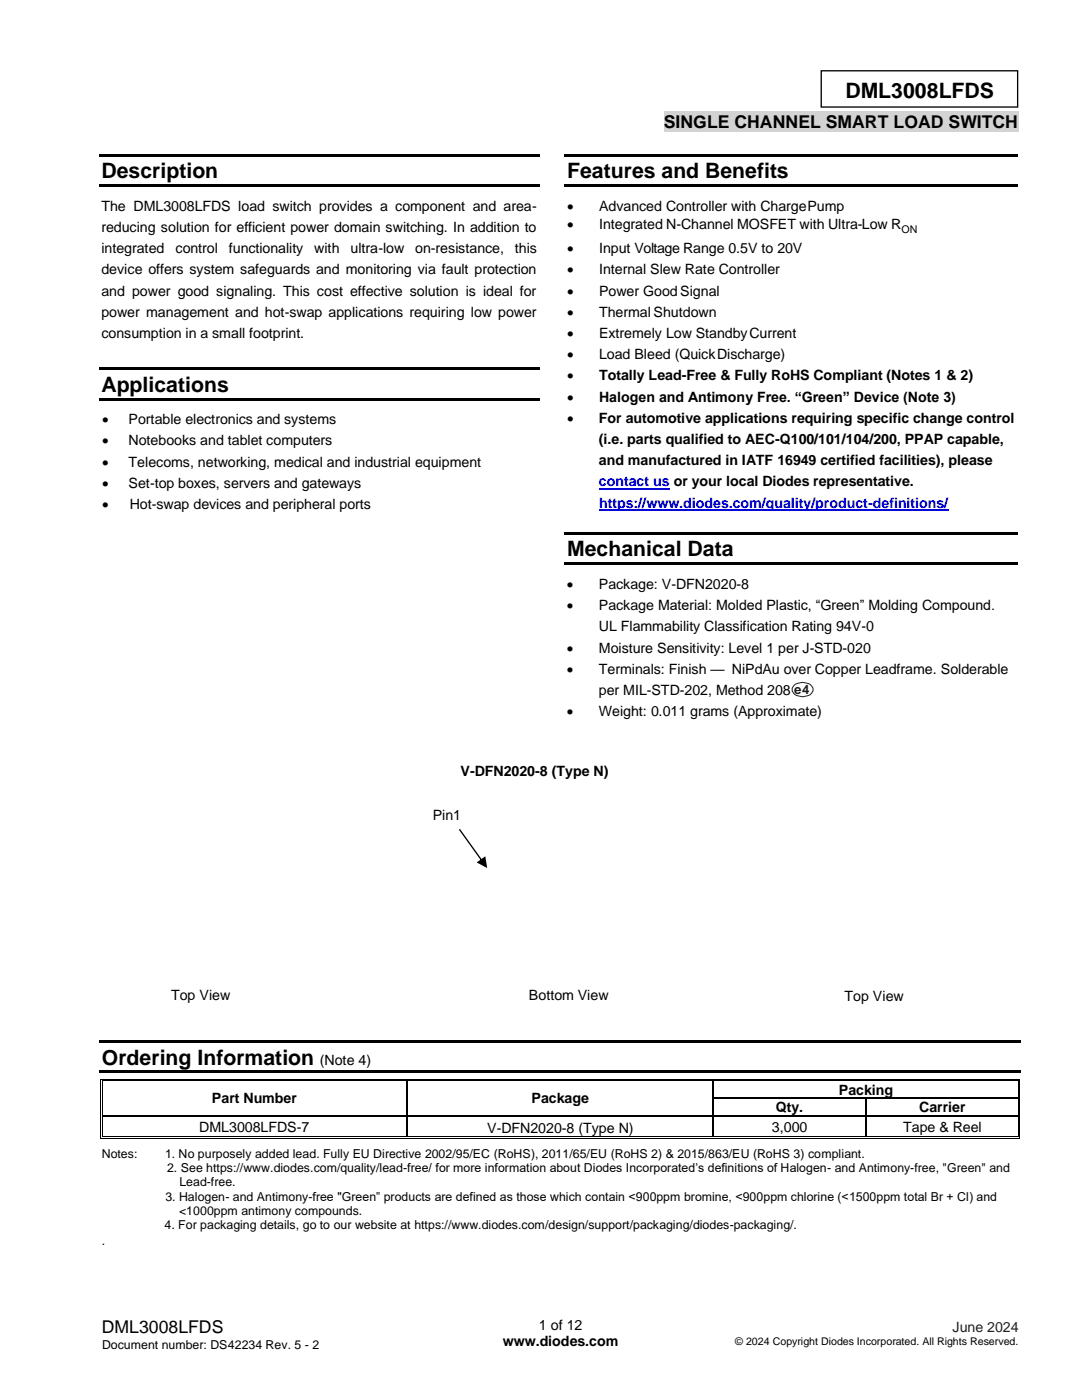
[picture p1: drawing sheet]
<svg xmlns="http://www.w3.org/2000/svg" width="216mm" height="279mm" viewBox="0 0 216 279" stroke-linecap="round" stroke-linejoin="round" font-family="sans-serif">
<defs><g id="words">
<g font-size="4.2">
<text x="168.7" y="19.5">DML3008LFDS</text>
<text x="182.3" y="24.4">6</text>
<text x="20.2" y="35.6">Description</text>
<text x="113.2" y="35.6">Features and Benefits</text>
<text x="20.2" y="78.2">Applications</text>
<text x="113.2" y="111.1">Mechanical Data</text>
<text x="20.3" y="212.5">Ordering Information</text>
</g>
<g font-size="3.5">
<text x="132.5" y="25.6">SINGLE CHANNEL SMART LOAD SWITCH</text>
<text x="20.3" y="266.1">DML3008LFDS</text>
</g>
<g font-size="2.8">
<text x="20.2" y="42">The DML3008LFDS load switch provides a component and area-</text>
<text x="20.2" y="46.3">reducing solution for efficient power domain switching. In addition to</text>
<text x="113.2" y="42">•</text>
<text x="113.2" y="45.7">•</text>
<text x="119.5" y="42">Advanced Controller with ChargePump</text>
<text x="119.5" y="45.7">Integrated N-Channel MOSFET with Ultra-Low R</text>
<text x="20.2" y="50.5">integrated</text>
<text x="35" y="50.5">control</text>
<text x="45.7" y="50.5">functionality</text>
<text x="62.7" y="50.5">with</text>
<text x="69.9" y="50.5">ultra-low</text>
<text x="82.9" y="50.5">on-resistance,</text>
<text x="102.7" y="50.5">this</text>
<text x="113.2" y="50.5">•</text>
<text x="119.5" y="50.5">Input Voltage Range 0.5V to 20V</text>
<text x="20.2" y="54.7">device offers system safeguards and monitoring via fault protection</text>
<text x="20.2" y="59">and power good signaling. This cost effective solution is ideal for</text>
<text x="113.2" y="54.7">•</text>
<text x="113.2" y="59">•</text>
<text x="119.5" y="54.7">Internal Slew Rate Controller</text>
<text x="119.5" y="59">Power Good Signal</text>
<text x="20.2" y="63.2">power management and hot-swap applications requiring low power</text>
<text x="113.2" y="63.2">•</text>
<text x="119.5" y="63.2">Thermal Shutdown</text>
<text x="20.2" y="67.4">consumption in a small footprint.</text>
<text x="113.2" y="67.4">•</text>
<text x="113.2" y="71.7">•</text>
<text x="119.5" y="67.4">Extremely Low StandbyCurrent</text>
<text x="119.5" y="71.7">Load Bleed (QuickDischarge)</text>
<text x="113.2" y="75.9">•</text>
<text x="119.5" y="75.9">Totally Lead-Free &amp; Fully RoHS Compliant (Notes 1 &amp; 2)</text>
<text x="113.2" y="80.1">•</text>
<text x="119.5" y="80.1">Halogen and Antimony Free. “Green” Device (Note 3)</text>
<text x="20.4" y="84.6">•</text>
<text x="20.4" y="88.9">•</text>
<text x="25.7" y="84.6">Portable electronics and systems</text>
<text x="25.7" y="88.9">Notebooks and tablet computers</text>
<text x="113.2" y="84.4">•</text>
<text x="119.5" y="84.4">For automotive applications requiring specific change control</text>
<text x="119.5" y="88.6">(i.e. parts qualified to AEC-Q100/101/104/200, PPAP capable,</text>
<text x="20.4" y="93.1">•</text>
<text x="25.7" y="93.1">Telecoms, networking, medical and industrial equipment</text>
<text x="119.5" y="92.9">and manufactured in IATF 16949 certified facilities), please</text>
<text x="20.4" y="97.3">•</text>
<text x="20.4" y="101.6">•</text>
<text x="25.7" y="97.3">Set-top boxes, servers and gateways</text>
<text x="25.9" y="101.6">Hot-swap devices and peripheral ports</text>
<text x="113.1" y="117.5">•</text>
<text x="119.5" y="117.5">Package: V-DFN2020-8</text>
<text x="113.1" y="121.8">•</text>
<text x="119.5" y="121.8">Package Material: Molded Plastic, “Green” Molding Compound.</text>
<text x="113.1" y="130.2">•</text>
<text x="119.5" y="126">UL Flammability Classification Rating 94V-0</text>
<text x="119.5" y="130.2">Moisture Sensitivity: Level 1 per J-STD-020</text>
<text x="113.1" y="134.5">•</text>
<text x="119.5" y="134.5">Terminals: Finish — NiPdAu over Copper Leadframe. Solderable</text>
<text x="113.1" y="142.9">•</text>
<text x="119.5" y="138.7">per MIL-STD-202, Method 208 e4</text>
<text x="119.5" y="142.9">Weight: 0.011 grams (Approximate)</text>
<text x="91.9" y="155">V-DFN2020-8 (Type N)</text>
<text x="86.3" y="163.6">Pin1</text>
<text x="34.1" y="199.5">Top View</text>
<text x="105.6" y="199.5">Bottom View</text>
<text x="168.5" y="199.8">Top View</text>
<text x="63.8" y="212.5">(Note 4)</text>
<text x="42.3" y="220.2">Part Number</text>
<text x="106.1" y="220.2">Package</text>
<text x="154.8" y="222">Qty.</text>
<text x="167.4" y="218.5">Packing</text>
<text x="183.4" y="222">Carrier</text>
<text x="39.8" y="225.8">DML3008LFDS-7</text>
<text x="97.2" y="226.2">V-DFN2020-8 (Type N)</text>
<text x="154" y="225.8">3,000</text>
<text x="180.2" y="225.8">Tape &amp; Reel</text>
<text x="100.3" y="268.7">www.diodes.com</text>
<text x="107.5" y="265.5">1 of 12</text>
</g>
<g font-size="2.8" fill="#00f">
<text x="119.5" y="97.1">contact us or your local Diodes representative.</text>
<text x="119.5" y="101.3">https://www.diodes.com/quality/product-definitions/</text>
</g>
<text font-size="2.8" fill="#231f20" x="190.1" y="265.8">June 2024</text>
<g font-size="2.5">
<text x="20.3" y="231">Notes:</text>
<text x="32.9" y="231">1. No purposely added lead. Fully EU Directive 2002/95/EC (RoHS), 2011/65/EU (RoHS 2) &amp; 2015/863/EU (RoHS 3) compliant.</text>
<text x="33.3" y="233.9">2. See https://www.diodes.com/quality/lead-free/ for more information about Diodes Incorporated’s definitions of Halogen- and Antimony-free, &quot;Green&quot; and</text>
<text x="33" y="239.6">3. Halogen- and Antimony-free &quot;Green” products are defined as those which contain &lt;900ppm bromine, &lt;900ppm chlorine (&lt;1500ppm total Br + Cl) and</text>
<text x="35.8" y="236.7">Lead-free.</text>
<text x="32.8" y="245.3">4. For packaging details, go to our website at https://www.diodes.com/design/support/packaging/diodes-packaging/.</text>
<text x="35.7" y="242.4">&lt;1000ppm antimony compounds.</text>
<text x="20.3" y="248.4">.</text>
<text x="20.4" y="269.2">Document number: DS42234 Rev. 5 - 2</text>
</g>
<g font-size="2.1">
<text x="179.9" y="46.4">ON</text>
<text x="146.7" y="268.4">© 2024 Copyright Diodes Incorporated. All Rights Reserved.</text>
</g>
</g></defs>
<path d="M163.9 14.1h39.2v7.3h-39.2z" fill="none" stroke="#000" stroke-width=".26"/>
<path d="M132.5 22.3h70.7v4.1h-70.7z" fill-rule="evenodd" fill="#d3d3d3"/>
<g fill="#000">
<path d="M19.7 30.7h87.9v.5h-87.9z" fill-rule="evenodd"/>
<path d="M19.7 36.8h87.9v.5h-87.9z" fill-rule="evenodd"/>
<path d="M112.7 30.7h90.4v.5h-90.4z" fill-rule="evenodd"/>
<path d="M112.7 36.8h90.4v.5h-90.4z" fill-rule="evenodd"/>
<path d="M19.7 73.4h87.9v.5h-87.9z" fill-rule="evenodd"/>
<path d="M19.7 79.4h87.9v.5h-87.9z" fill-rule="evenodd"/>
<path d="M112.7 106.2h90.4v.5h-90.4z" fill-rule="evenodd"/>
<path d="M112.7 112.3h90.4v.5h-90.4z" fill-rule="evenodd"/>
<path d="M19.8 207.6h183.9v.5h-183.9z" fill-rule="evenodd"/>
<path d="M19.8 213.7h183.9v.5h-183.9z" fill-rule="evenodd"/>
<path d="M20 215.3h.2v.5h-.2z" fill-rule="evenodd"/>
<path d="M20 215.3h.5v.2h-.5z" fill-rule="evenodd"/>
<path d="M20 219.1h.2v.2h-.2z" fill-rule="evenodd"/>
<path d="M20.3 215.6h.2v.2h-.2z" fill-rule="evenodd"/>
<path d="M20.3 215.6h.2v.2h-.2z" fill-rule="evenodd"/>
<path d="M20.3 219.1h.2v.2h-.2z" fill-rule="evenodd"/>
<path d="M81.2 215.8h.2z" fill-rule="evenodd"/>
<path d="M81.2 215.3h.5v.2h-.5z" fill-rule="evenodd"/>
<path d="M81.2 215.6h.5v.2h-.5z" fill-rule="evenodd"/>
<path d="M81.2 219.1h.2v.2h-.2z" fill-rule="evenodd"/>
<path d="M142.2 215.8h.2z" fill-rule="evenodd"/>
<path d="M142.2 215.3h.5v.2h-.5z" fill-rule="evenodd"/>
<path d="M142.2 215.6h.5v.2h-.5z" fill-rule="evenodd"/>
<path d="M142.2 219.1h.2v.2h-.2z" fill-rule="evenodd"/>
<path d="M172.7 219.1h.2v.2h-.2z" fill-rule="evenodd"/>
<path d="M203.1 215.3h.5v.2h-.5z" fill-rule="evenodd"/>
<path d="M203.1 215.6h.1v.2h-.1z" fill-rule="evenodd"/>
<path d="M203.1 215.6h.1v.2h-.1z" fill-rule="evenodd"/>
<path d="M203.1 219.1h.1v.2h-.1z" fill-rule="evenodd"/>
<path d="M203.4 215.3h.2v.5h-.2z" fill-rule="evenodd"/>
<path d="M203.4 219.1h.2v.2h-.2z" fill-rule="evenodd"/>
<path d="M20 222.6h.2v.2h-.2z" fill-rule="evenodd"/>
<path d="M20 226.8h.2v.5h-.2z" fill-rule="evenodd"/>
<path d="M20 227.2h.5v.1h-.5z" fill-rule="evenodd"/>
<path d="M20.3 222.6h.2v.2h-.2z" fill-rule="evenodd"/>
<path d="M20.3 226.8h.2v.2h-.2z" fill-rule="evenodd"/>
<path d="M20.3 226.8h.2v.2h-.2z" fill-rule="evenodd"/>
<path d="M81.2 222.6h.2v.2h-.2z" fill-rule="evenodd"/>
<path d="M81.2 226.8h.5v.2h-.5z" fill-rule="evenodd"/>
<path d="M81.2 227.2h.5v.1h-.5z" fill-rule="evenodd"/>
<path d="M142.2 222.6h.2v.2h-.2z" fill-rule="evenodd"/>
<path d="M142.2 226.8h.5v.2h-.5z" fill-rule="evenodd"/>
<path d="M142.2 227.2h.5v.1h-.5z" fill-rule="evenodd"/>
<path d="M172.7 222.6h.2v.2h-.2z" fill-rule="evenodd"/>
<path d="M172.7 226.8h.5v.2h-.5z" fill-rule="evenodd"/>
<path d="M172.7 227.2h.5v.1h-.5z" fill-rule="evenodd"/>
<path d="M203.1 222.6h.1v.2h-.1z" fill-rule="evenodd"/>
<path d="M203.1 227.2h.5v.1h-.5z" fill-rule="evenodd"/>
<path d="M203.1 226.8h.1v.2h-.1z" fill-rule="evenodd"/>
<path d="M203.1 226.8h.1v.2h-.1z" fill-rule="evenodd"/>
<path d="M203.4 222.6h.2v.2h-.2z" fill-rule="evenodd"/>
<path d="M203.4 226.8h.2v.5h-.2z" fill-rule="evenodd"/>
</g>
<path d="M119.5 97.5h14.1M119.5 101.8h69.7" fill="none" stroke="#00f" stroke-width=".3"/>
<g fill="none" stroke="#000" stroke-width=".2">
<path d="M20.1 215.8v3.3M20.1 219.3v3.3M20.4 215.8v3.3M20.4 219.3v3.3M20.5 215.4h60.7M20.5 215.7h60.7M81.7 215.4h60.5M81.7 215.7h60.5M142.7 215.4h60.4M142.7 215.7h60.4M203.2 215.8v3.3M203.2 219.3v3.3"/>
<path d="M203.5 215.8v3.3M203.5 219.3v3.3M20.1 222.8v4M20.4 222.8v4M20.5 227.2h60.7M20.5 226.9h60.7M81.7 227.2h60.5M81.7 226.9h60.5M142.7 227.2h30M142.7 226.9h30M173.2 227.2h29.9M173.2 226.9h29.9"/>
<path d="M203.2 222.8v4M203.5 222.8v4"/>
</g>
<g fill="none" stroke="#000" stroke-width=".25">
<path d="M81.3 215.8v3.3M81.3 219.3v3.3M142.3 215.8v3.3M142.3 219.3v3.3M142.4 219.2h30.3M172.8 219.3v3.3M172.9 219.2h30.2M20.5 222.7h60.7M81.3 222.8v4M81.4 222.7h60.8M142.3 222.8v4M142.4 222.7h30.3"/>
<path d="M172.8 222.8v4M172.9 222.7h30.2"/>
</g>
<path d="M158.6 136.6a2.77 2.77 0 0 1 3.3 .2 1.2 1.2 0 0 1 .2 1.4 1.2 1.2 0 0 1-1.1 .7 2.47 2.47 0 0 1-2.9-1 1.17 1.17 0 0 1 .5-1.3z" fill="none" stroke="#1f1a17" stroke-width=".2"/>
<path d="M91.6 165.6l.2-.2 4.5 6.3-.2 .2zM95.1 172.1l1.7-1.2 .4 2.3z" fill="#000"/>
<use href="#words"/>
</svg>
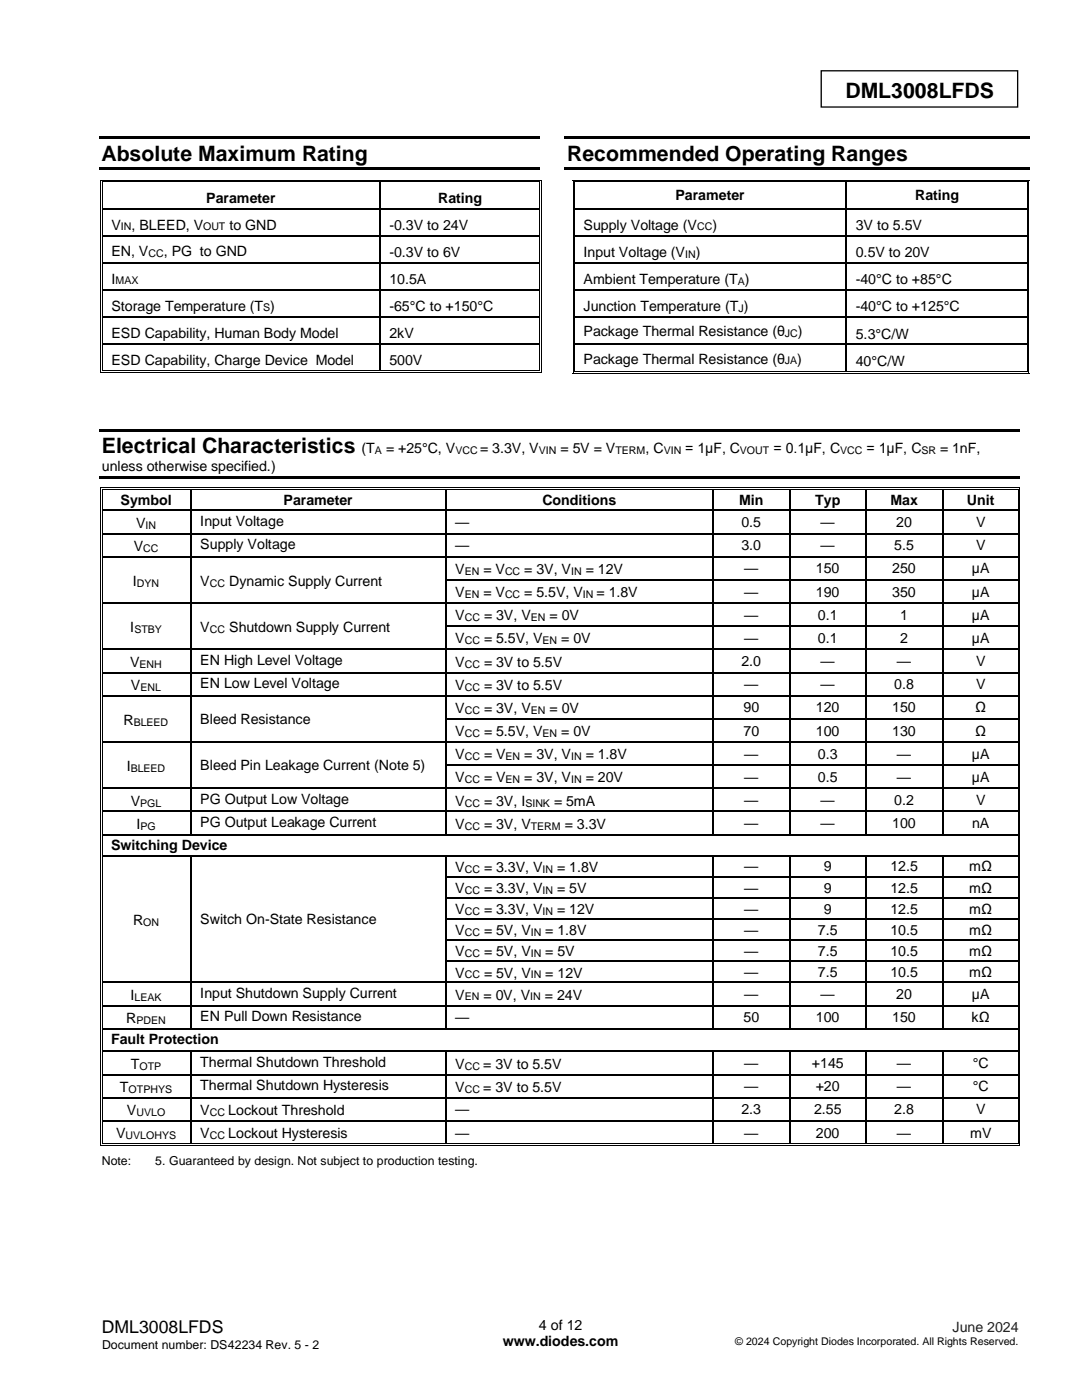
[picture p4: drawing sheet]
<svg xmlns="http://www.w3.org/2000/svg" width="216mm" height="279mm" viewBox="0 0 216 279" stroke-linecap="round" stroke-linejoin="round" font-family="sans-serif">
<defs><g id="words">
<g font-size="4.2">
<text x="168.7" y="19.5">DML3008LFDS</text>
<text x="182.3" y="24.4">6</text>
<text x="20.2" y="32.1">Absolute Maximum Rating</text>
<text x="113.2" y="32.1">Recommended Operating Ranges</text>
<text x="20.3" y="90.4">Electrical Characteristics</text>
</g>
<text font-size="3.5" x="20.3" y="266.1">DML3008LFDS</text>
<g font-size="2.8">
<text x="41.2" y="40.5">Parameter</text>
<text x="87.4" y="40.5">Rating</text>
<text x="134.8" y="40">Parameter</text>
<text x="182.6" y="40">Rating</text>
<text x="22.2" y="45.8">V</text>
<text x="26.3" y="45.8">, BLEED, V</text>
<text x="45.8" y="45.8">to GND</text>
<text x="77.7" y="45.9">-0.3V to 24V</text>
<text x="116.4" y="45.8">Supply Voltage (V</text>
<text x="142.1" y="45.8">)</text>
<text x="170.8" y="45.9">3V to 5.5V</text>
<text x="22.2" y="51.2">EN, V</text>
<text x="32.7" y="51.2">, PG to GND</text>
<text x="77.7" y="51.3">-0.3V to 6V</text>
<text x="116.4" y="51.2">Input Voltage (V</text>
<text x="138.8" y="51.2">)</text>
<text x="170.8" y="51.3">0.5V to 20V</text>
<text x="22.2" y="56.6">I</text>
<text x="77.7" y="56.7">10.5A</text>
<text x="116.4" y="56.6">Ambient Temperature (T )</text>
<text x="170.8" y="56.7">-40°C to +85°C</text>
<text x="22.2" y="62">Storage Temperature (T )</text>
<text x="77.7" y="62.1">-65°C to +150°C</text>
<text x="116.4" y="62.1">Junction Temperature (T )</text>
<text x="170.8" y="62.2">-40°C to +125°C</text>
<text x="22.2" y="67.5">ESD Capability, Human Body Model</text>
<text x="77.7" y="67.5">2kV</text>
<text x="116.4" y="67.1">Package Thermal Resistance (θ</text>
<text x="159.2" y="67.1">)</text>
<text x="170.8" y="67.6">5.3°C/W</text>
<text x="22.2" y="72.9">ESD Capability, Charge Device Model</text>
<text x="77.7" y="72.9">500V</text>
<text x="116.4" y="72.6">Package Thermal Resistance (θ</text>
<text x="159.1" y="72.6">)</text>
<text x="170.8" y="72.9">40°C/W</text>
<text x="20.3" y="94">unless otherwise specified.)</text>
<text x="72.2" y="90.4">(T</text>
<text x="77" y="90.4">= +25°C, V</text>
<text x="95.8" y="90.4">= 3.3V, V</text>
<text x="111.8" y="90.4">= 5V = V</text>
<text x="128.8" y="90.4">, C</text>
<text x="136.7" y="90.4">= 1μF, C</text>
<text x="154.3" y="90.4">= 0.1μF, C</text>
<text x="172.9" y="90.4">= 1μF, C</text>
<text x="187.6" y="90.4">= 1nF,</text>
<text x="24.1" y="100.8">Symbol</text>
<text x="56.6" y="100.8">Parameter</text>
<text x="108.2" y="100.8">Conditions</text>
<text x="147.5" y="100.8">Min</text>
<text x="162.6" y="100.8">Typ</text>
<text x="177.7" y="100.8">Max</text>
<text x="192.9" y="100.8">Unit</text>
<text x="27.1" y="105.3">V</text>
<text x="40" y="105">Input Voltage</text>
<text x="90.8" y="105.2">—</text>
<text x="147.9" y="105.2">0.5</text>
<text x="163.7" y="105.2">—</text>
<text x="178.9" y="105.2">20</text>
<text x="194.8" y="105.2">V</text>
<text x="26.7" y="110">V</text>
<text x="40" y="109.6">Supply Voltage</text>
<text x="90.8" y="109.8">—</text>
<text x="147.9" y="109.8">3.0</text>
<text x="163.7" y="109.8">—</text>
<text x="178.4" y="109.8">5.5</text>
<text x="194.8" y="109.8">V</text>
<text x="26.5" y="116.9">I</text>
<text x="40" y="116.9">V</text>
<text x="45.7" y="116.9">Dynamic Supply Current</text>
<text x="90.8" y="114.6">V</text>
<text x="90.8" y="119.2">V</text>
<text x="96.5" y="114.6">= V</text>
<text x="96.5" y="119.2">= V</text>
<text x="104.6" y="114.6">= 3V, V</text>
<text x="104.6" y="119.2">= 5.5V, V</text>
<text x="116.9" y="114.6">= 12V</text>
<text x="119" y="119.2">= 1.8V</text>
<text x="148.5" y="114.4">—</text>
<text x="148.5" y="119.1">—</text>
<text x="162.8" y="114.4">150</text>
<text x="162.8" y="119.1">190</text>
<text x="178" y="114.4">250</text>
<text x="178" y="119.1">350</text>
<text x="193.9" y="114.4">µA</text>
<text x="193.9" y="119.1">µA</text>
<text x="90.8" y="123.8">V</text>
<text x="96.6" y="123.8">= 3V, V</text>
<text x="109.7" y="123.8">= 0V</text>
<text x="148.5" y="123.7">—</text>
<text x="163.2" y="123.7">0.1</text>
<text x="179.6" y="123.7">1</text>
<text x="193.9" y="123.7">µA</text>
<text x="26" y="126.1">I</text>
<text x="40" y="126.1">V</text>
<text x="45.7" y="126.1">Shutdown Supply Current</text>
<text x="90.8" y="128.4">V</text>
<text x="96.6" y="128.4">= 5.5V, V</text>
<text x="112" y="128.4">= 0V</text>
<text x="148.5" y="128.3">—</text>
<text x="163.2" y="128.3">0.1</text>
<text x="179.6" y="128.3">2</text>
<text x="193.9" y="128.3">µA</text>
<text x="26" y="133.1">V</text>
<text x="26.1" y="137.7">V</text>
<text x="40" y="132.7">EN High Level Voltage</text>
<text x="40" y="137.3">EN Low Level Voltage</text>
<text x="90.8" y="133.1">V</text>
<text x="90.8" y="137.7">V</text>
<text x="96.6" y="133.1">= 3V to 5.5V</text>
<text x="96.6" y="137.7">= 3V to 5.5V</text>
<text x="147.9" y="132.9">2.0</text>
<text x="148.5" y="137.6">—</text>
<text x="163.7" y="132.9">—</text>
<text x="163.7" y="137.6">—</text>
<text x="178.4" y="137.6">0.8</text>
<text x="179" y="132.9">—</text>
<text x="194.8" y="132.9">V</text>
<text x="194.8" y="137.6">V</text>
<text x="90.8" y="142.3">V</text>
<text x="96.6" y="142.3">= 3V, V</text>
<text x="109.7" y="142.3">= 0V</text>
<text x="148.4" y="142.2">90</text>
<text x="162.8" y="142.2">120</text>
<text x="178" y="142.2">150</text>
<text x="194.6" y="142.2">Ω</text>
<text x="24.6" y="144.6">R</text>
<text x="40" y="144.5">Bleed Resistance</text>
<text x="90.8" y="146.9">V</text>
<text x="96.6" y="146.9">= 5.5V, V</text>
<text x="112" y="146.9">= 0V</text>
<text x="148.4" y="146.8">70</text>
<text x="162.8" y="146.8">100</text>
<text x="178" y="146.8">130</text>
<text x="194.6" y="146.8">Ω</text>
<text x="25.3" y="153.9">I</text>
<text x="40" y="153.7">Bleed Pin Leakage Current (Note 5)</text>
<text x="90.8" y="151.5">V</text>
<text x="96.6" y="151.5">= V</text>
<text x="104.6" y="151.5">= 3V, V</text>
<text x="116.9" y="151.5">= 1.8V</text>
<text x="148.5" y="151.4">—</text>
<text x="163.2" y="151.4">0.3</text>
<text x="179" y="151.4">—</text>
<text x="193.9" y="151.4">µA</text>
<text x="26.1" y="160.8">V</text>
<text x="40" y="160.5">PG Output Low Voltage</text>
<text x="90.8" y="156.2">V</text>
<text x="90.8" y="160.8">V</text>
<text x="96.6" y="156.2">= V</text>
<text x="96.6" y="160.8">= 3V, I</text>
<text x="104.6" y="156.2">= 3V, V</text>
<text x="110.5" y="160.8">= 5mA</text>
<text x="116.9" y="156.2">= 20V</text>
<text x="148.5" y="156">—</text>
<text x="148.5" y="160.6">—</text>
<text x="163.2" y="156">0.5</text>
<text x="163.7" y="160.6">—</text>
<text x="178.4" y="160.6">0.2</text>
<text x="179" y="156">—</text>
<text x="193.9" y="156">µA</text>
<text x="194.8" y="160.6">V</text>
<text x="27.2" y="165.4">I</text>
<text x="40" y="165.1">PG Output Leakage Current</text>
<text x="90.8" y="165.4">V</text>
<text x="96.6" y="165.4">= 3V, V</text>
<text x="112.7" y="165.4">= 3.3V</text>
<text x="148.5" y="165.3">—</text>
<text x="163.7" y="165.3">—</text>
<text x="178" y="165.3">100</text>
<text x="194" y="165.3">nA</text>
<text x="22.1" y="169.7">Switching Device</text>
<text x="148.5" y="173.9">—</text>
<text x="164.4" y="173.9">9</text>
<text x="177.7" y="173.9">12.5</text>
<text x="193.4" y="173.9">mΩ</text>
<text x="90.8" y="174">V</text>
<text x="90.8" y="178.2">V</text>
<text x="96.6" y="174">= 3.3V, V</text>
<text x="96.6" y="178.2">= 3.3V, V</text>
<text x="111.2" y="174">= 1.8V</text>
<text x="111.2" y="178.2">= 5V</text>
<text x="148.5" y="178.1">—</text>
<text x="164.4" y="178.1">9</text>
<text x="177.7" y="178.1">12.5</text>
<text x="193.4" y="178.1">mΩ</text>
<text x="26.6" y="184.6">R</text>
<text x="40" y="184.4">Switch On-State Resistance</text>
<text x="90.8" y="182.4">V</text>
<text x="96.6" y="182.4">= 3.3V, V</text>
<text x="111.2" y="182.4">= 12V</text>
<text x="148.5" y="182.4">—</text>
<text x="164.4" y="182.4">9</text>
<text x="177.7" y="182.4">12.5</text>
<text x="193.4" y="182.4">mΩ</text>
<text x="90.8" y="186.7">V</text>
<text x="90.8" y="190.9">V</text>
<text x="96.6" y="186.7">= 5V, V</text>
<text x="96.6" y="190.9">= 5V, V</text>
<text x="108.8" y="186.7">= 1.8V</text>
<text x="108.8" y="190.9">= 5V</text>
<text x="148.5" y="186.5">—</text>
<text x="148.5" y="190.8">—</text>
<text x="163.2" y="186.5">7.5</text>
<text x="163.2" y="190.8">7.5</text>
<text x="177.7" y="186.5">10.5</text>
<text x="177.7" y="190.8">10.5</text>
<text x="193.4" y="186.5">mΩ</text>
<text x="193.4" y="190.8">mΩ</text>
<text x="90.8" y="195.1">V</text>
<text x="96.6" y="195.1">= 5V, V</text>
<text x="108.8" y="195.1">= 12V</text>
<text x="148.5" y="195">—</text>
<text x="163.2" y="195">7.5</text>
<text x="177.7" y="195">10.5</text>
<text x="193.4" y="195">mΩ</text>
<text x="26" y="199.5">I</text>
<text x="40" y="199.2">Input Shutdown Supply Current</text>
<text x="40" y="203.8">EN Pull Down Resistance</text>
<text x="90.8" y="199.5">V</text>
<text x="96.5" y="199.5">= 0V, V</text>
<text x="108.7" y="199.5">= 24V</text>
<text x="148.5" y="199.4">—</text>
<text x="163.7" y="199.4">—</text>
<text x="178.9" y="199.4">20</text>
<text x="193.9" y="199.4">µA</text>
<text x="22.1" y="208.4">Fault Protection</text>
<text x="25.2" y="204.2">R</text>
<text x="90.8" y="204">—</text>
<text x="148.4" y="204">50</text>
<text x="162.8" y="204">100</text>
<text x="178" y="204">150</text>
<text x="193.9" y="204">kΩ</text>
<text x="26.1" y="213.3">T</text>
<text x="40" y="213">Thermal Shutdown Threshold</text>
<text x="90.8" y="213.3">V</text>
<text x="96.4" y="213.3">= 3V to 5.5V</text>
<text x="148.5" y="213.2">—</text>
<text x="162" y="213.2">+145</text>
<text x="179" y="213.2">—</text>
<text x="194.1" y="213.2">°C</text>
<text x="23.9" y="218">T</text>
<text x="40" y="217.6">Thermal Shutdown Hysteresis</text>
<text x="90.8" y="218">V</text>
<text x="96.4" y="218">= 3V to 5.5V</text>
<text x="148.5" y="217.8">—</text>
<text x="162.8" y="217.8">+20</text>
<text x="179" y="217.8">—</text>
<text x="194.1" y="217.8">°C</text>
<text x="23.2" y="227.2">V</text>
<text x="25.3" y="222.6">V</text>
<text x="40" y="222.6">V</text>
<text x="40" y="227.2">V</text>
<text x="45.6" y="222.6">Lockout Threshold</text>
<text x="45.6" y="227.2">Lockout Hysteresis</text>
<text x="90.8" y="222.4">—</text>
<text x="90.8" y="227.1">—</text>
<text x="147.9" y="222.4">2.3</text>
<text x="148.5" y="227.1">—</text>
<text x="162.4" y="222.4">2.55</text>
<text x="162.8" y="227.1">200</text>
<text x="178.4" y="222.4">2.8</text>
<text x="179" y="227.1">—</text>
<text x="193.6" y="227.1">mV</text>
<text x="194.8" y="222.4">V</text>
<text x="100.3" y="268.7">www.diodes.com</text>
<text x="107.5" y="265.5">4 of 12</text>
</g>
<text font-size="2.8" fill="#231f20" x="190.1" y="265.8">June 2024</text>
<g font-size="2.5">
<text x="20.3" y="232.4">Note:</text>
<text x="31" y="232.4">5. Guaranteed by design. Not subject to production testing.</text>
<text x="20.4" y="269.2">Document number: DS42234 Rev. 5 - 2</text>
</g>
<g font-size="2.1">
<text x="24.1" y="46">IN</text>
<text x="40.6" y="46">OUT</text>
<text x="139.1" y="46">CC</text>
<text x="29.6" y="51.4">CC</text>
<text x="136.7" y="51.4">IN</text>
<text x="23" y="56.8">MAX</text>
<text x="147.2" y="56.8">A</text>
<text x="52.5" y="62.2">S</text>
<text x="147.4" y="62.2">J</text>
<text x="156.6" y="67.3">JC</text>
<text x="156.6" y="72.7">JA</text>
<text x="74.8" y="90.6">A</text>
<text x="90.9" y="90.6">VCC</text>
<text x="107.5" y="90.6">VIN</text>
<text x="122.8" y="90.6">TERM</text>
<text x="132.4" y="90.6">VIN</text>
<text x="147.6" y="90.6">VOUT</text>
<text x="167.7" y="90.6">VCC</text>
<text x="183.9" y="90.6">SR</text>
<text x="29" y="105.5">IN</text>
<text x="28.6" y="110.1">CC</text>
<text x="27.3" y="117.1">DYN</text>
<text x="41.9" y="117.1">CC</text>
<text x="92.7" y="114.7">EN</text>
<text x="92.7" y="119.4">EN</text>
<text x="100.8" y="114.7">CC</text>
<text x="100.8" y="119.4">CC</text>
<text x="114" y="114.7">IN</text>
<text x="116.3" y="119.4">IN</text>
<text x="92.7" y="124">CC</text>
<text x="105.9" y="124">EN</text>
<text x="26.8" y="126.3">STBY</text>
<text x="41.9" y="126.3">CC</text>
<text x="92.7" y="128.6">CC</text>
<text x="108.3" y="128.6">EN</text>
<text x="27.9" y="133.2">ENH</text>
<text x="28" y="137.9">ENL</text>
<text x="92.7" y="133.2">CC</text>
<text x="92.7" y="137.9">CC</text>
<text x="92.7" y="142.5">CC</text>
<text x="105.9" y="142.5">EN</text>
<text x="26.7" y="144.8">BLEED</text>
<text x="92.7" y="147.1">CC</text>
<text x="108.3" y="147.1">EN</text>
<text x="26.1" y="154">BLEED</text>
<text x="92.7" y="151.7">CC</text>
<text x="100.9" y="151.7">EN</text>
<text x="114" y="151.7">IN</text>
<text x="28" y="161">PGL</text>
<text x="92.7" y="156.3">CC</text>
<text x="92.7" y="161">CC</text>
<text x="100.9" y="156.3">EN</text>
<text x="104.8" y="161">SINK</text>
<text x="114" y="156.3">IN</text>
<text x="28" y="165.6">PG</text>
<text x="92.7" y="165.6">CC</text>
<text x="105.9" y="165.6">TERM</text>
<text x="92.7" y="174.2">CC</text>
<text x="92.7" y="178.4">CC</text>
<text x="108.3" y="174.2">IN</text>
<text x="108.3" y="178.4">IN</text>
<text x="28.6" y="184.8">ON</text>
<text x="92.7" y="182.6">CC</text>
<text x="108.3" y="182.6">IN</text>
<text x="92.7" y="186.8">CC</text>
<text x="92.7" y="191">CC</text>
<text x="105.9" y="186.8">IN</text>
<text x="105.9" y="191">IN</text>
<text x="92.7" y="195.3">CC</text>
<text x="105.9" y="195.3">IN</text>
<text x="26.8" y="199.7">LEAK</text>
<text x="92.7" y="199.7">EN</text>
<text x="105.8" y="199.7">IN</text>
<text x="27.2" y="204.3">PDEN</text>
<text x="27.8" y="213.5">OTP</text>
<text x="92.7" y="213.5">CC</text>
<text x="25.7" y="218.1">OTPHYS</text>
<text x="92.7" y="218.1">CC</text>
<text x="25.1" y="227.4">UVLOHYS</text>
<text x="27.2" y="222.8">UVLO</text>
<text x="41.9" y="222.8">CC</text>
<text x="41.9" y="227.4">CC</text>
<text x="146.7" y="268.4">© 2024 Copyright Diodes Incorporated. All Rights Reserved.</text>
</g>
</g></defs>
<path d="M163.9 14.1h39.2v7.3h-39.2z" fill="none" stroke="#000" stroke-width=".26"/>
<g fill="#000">
<path d="M19.7 27.2h87.9v.5h-87.9z" fill-rule="evenodd"/>
<path d="M19.7 33.3h87.9v.5h-87.9z" fill-rule="evenodd"/>
<path d="M20.1 35.9h.1v.5h-.1z" fill-rule="evenodd"/>
<path d="M20.1 35.9h.5v.1h-.5z" fill-rule="evenodd"/>
<path d="M20.4 36.2h.2v.2h-.2z" fill-rule="evenodd"/>
<path d="M20.4 36.2h.2v.2h-.2z" fill-rule="evenodd"/>
<path d="M75.7 36.4h.2z" fill-rule="evenodd"/>
<path d="M75.7 35.9h.5v.1h-.5z" fill-rule="evenodd"/>
<path d="M75.7 36.2h.5v.2h-.5z" fill-rule="evenodd"/>
<path d="M107.6 35.9h.5v.1h-.5z" fill-rule="evenodd"/>
<path d="M107.6 36.2h.2v.2h-.2z" fill-rule="evenodd"/>
<path d="M107.6 36.2h.2v.2h-.2z" fill-rule="evenodd"/>
<path d="M107.9 35.9h.2v.5h-.2z" fill-rule="evenodd"/>
<path d="M112.7 27.2h92.7v.5h-92.7z" fill-rule="evenodd"/>
<path d="M112.7 33.3h92.7v.5h-92.7z" fill-rule="evenodd"/>
<path d="M114.3 35.9h.1v.5h-.1z" fill-rule="evenodd"/>
<path d="M114.3 35.9h.5v.1h-.5z" fill-rule="evenodd"/>
<path d="M114.6 36.2h.2v.2h-.2z" fill-rule="evenodd"/>
<path d="M114.6 36.2h.2v.2h-.2z" fill-rule="evenodd"/>
<path d="M168.7 36.4h.3z" fill-rule="evenodd"/>
<path d="M168.7 35.9h.5v.1h-.5z" fill-rule="evenodd"/>
<path d="M168.7 36.2h.5v.2h-.5z" fill-rule="evenodd"/>
<path d="M204.9 35.9h.5v.1h-.5z" fill-rule="evenodd"/>
<path d="M204.9 36.2h.2v.2h-.2z" fill-rule="evenodd"/>
<path d="M204.9 36.2h.2v.2h-.2z" fill-rule="evenodd"/>
<path d="M205.2 35.9h.2v.5h-.2z" fill-rule="evenodd"/>
<path d="M20.1 41.5h.1v.3h-.1z" fill-rule="evenodd"/>
<path d="M20.1 46.9h.1v.3h-.1z" fill-rule="evenodd"/>
<path d="M20.1 52.3h.1v.3h-.1z" fill-rule="evenodd"/>
<path d="M20.1 57.7h.1v.3h-.1z" fill-rule="evenodd"/>
<path d="M20.4 41.5h.2v.3h-.2z" fill-rule="evenodd"/>
<path d="M20.4 46.9h.2v.3h-.2z" fill-rule="evenodd"/>
<path d="M20.4 52.3h.2v.3h-.2z" fill-rule="evenodd"/>
<path d="M20.4 57.7h.2v.3h-.2z" fill-rule="evenodd"/>
<path d="M75.7 41.5h.2v.3h-.2z" fill-rule="evenodd"/>
<path d="M75.7 46.9h.2v.3h-.2z" fill-rule="evenodd"/>
<path d="M75.7 52.3h.2v.3h-.2z" fill-rule="evenodd"/>
<path d="M75.7 57.7h.2v.3h-.2z" fill-rule="evenodd"/>
<path d="M107.6 41.5h.2v.3h-.2z" fill-rule="evenodd"/>
<path d="M107.6 46.9h.2v.3h-.2z" fill-rule="evenodd"/>
<path d="M107.6 52.3h.2v.3h-.2z" fill-rule="evenodd"/>
<path d="M107.6 57.7h.2v.3h-.2z" fill-rule="evenodd"/>
<path d="M107.9 41.5h.2v.3h-.2z" fill-rule="evenodd"/>
<path d="M107.9 46.9h.2v.3h-.2z" fill-rule="evenodd"/>
<path d="M107.9 52.3h.2v.3h-.2z" fill-rule="evenodd"/>
<path d="M107.9 57.7h.2v.3h-.2z" fill-rule="evenodd"/>
<path d="M114.3 41.5h.1v.3h-.1z" fill-rule="evenodd"/>
<path d="M114.3 47h.1v.2h-.1z" fill-rule="evenodd"/>
<path d="M114.3 52.4h.1v.2h-.1z" fill-rule="evenodd"/>
<path d="M114.3 57.8h.1v.2h-.1z" fill-rule="evenodd"/>
<path d="M114.6 41.5h.2v.3h-.2z" fill-rule="evenodd"/>
<path d="M114.6 47h.2v.2h-.2z" fill-rule="evenodd"/>
<path d="M114.6 52.4h.2v.2h-.2z" fill-rule="evenodd"/>
<path d="M114.6 57.8h.2v.2h-.2z" fill-rule="evenodd"/>
<path d="M168.7 41.5h.3v.3h-.3z" fill-rule="evenodd"/>
<path d="M168.7 47h.3v.2h-.3z" fill-rule="evenodd"/>
<path d="M168.7 52.4h.3v.2h-.3z" fill-rule="evenodd"/>
<path d="M168.7 57.8h.3v.2h-.3z" fill-rule="evenodd"/>
<path d="M204.9 41.5h.2v.3h-.2z" fill-rule="evenodd"/>
<path d="M204.9 47h.2v.2h-.2z" fill-rule="evenodd"/>
<path d="M204.9 52.4h.2v.2h-.2z" fill-rule="evenodd"/>
<path d="M204.9 57.8h.2v.2h-.2z" fill-rule="evenodd"/>
<path d="M205.2 41.5h.2v.3h-.2z" fill-rule="evenodd"/>
<path d="M205.2 47h.2v.2h-.2z" fill-rule="evenodd"/>
<path d="M205.2 52.4h.2v.2h-.2z" fill-rule="evenodd"/>
<path d="M205.2 57.8h.2v.2h-.2z" fill-rule="evenodd"/>
<path d="M20.1 63.1h.1v.3h-.1z" fill-rule="evenodd"/>
<path d="M20.1 68.5h.1v.3h-.1z" fill-rule="evenodd"/>
<path d="M20.1 73.9h.1v.5h-.1z" fill-rule="evenodd"/>
<path d="M20.1 74.3h.5v.1h-.5z" fill-rule="evenodd"/>
<path d="M20.4 63.1h.2v.3h-.2z" fill-rule="evenodd"/>
<path d="M20.4 68.5h.2v.3h-.2z" fill-rule="evenodd"/>
<path d="M20.4 73.9h.2v.2h-.2z" fill-rule="evenodd"/>
<path d="M20.4 73.9h.2v.2h-.2z" fill-rule="evenodd"/>
<path d="M75.7 63.1h.2v.3h-.2z" fill-rule="evenodd"/>
<path d="M75.7 68.5h.2v.3h-.2z" fill-rule="evenodd"/>
<path d="M75.7 73.9h.5v.2h-.5z" fill-rule="evenodd"/>
<path d="M75.7 74.3h.5v.1h-.5z" fill-rule="evenodd"/>
<path d="M107.6 63.1h.2v.3h-.2z" fill-rule="evenodd"/>
<path d="M107.6 68.5h.2v.3h-.2z" fill-rule="evenodd"/>
<path d="M107.6 74.3h.5v.1h-.5z" fill-rule="evenodd"/>
<path d="M107.6 73.9h.2v.2h-.2z" fill-rule="evenodd"/>
<path d="M107.6 73.9h.2v.2h-.2z" fill-rule="evenodd"/>
<path d="M107.9 63.1h.2v.3h-.2z" fill-rule="evenodd"/>
<path d="M107.9 68.5h.2v.3h-.2z" fill-rule="evenodd"/>
<path d="M107.9 73.9h.2v.5h-.2z" fill-rule="evenodd"/>
<path d="M114.3 63.2h.1v.2h-.1z" fill-rule="evenodd"/>
<path d="M114.3 68.6h.1v.2h-.1z" fill-rule="evenodd"/>
<path d="M114.3 74h.1v.6h-.1z" fill-rule="evenodd"/>
<path d="M114.3 74.4h.5v.2h-.5z" fill-rule="evenodd"/>
<path d="M114.6 63.2h.2v.2h-.2z" fill-rule="evenodd"/>
<path d="M114.6 68.6h.2v.2h-.2z" fill-rule="evenodd"/>
<path d="M114.6 74h.2v.2h-.2z" fill-rule="evenodd"/>
<path d="M114.6 74h.2v.2h-.2z" fill-rule="evenodd"/>
<path d="M168.7 63.2h.3v.2h-.3z" fill-rule="evenodd"/>
<path d="M168.7 68.6h.3v.2h-.3z" fill-rule="evenodd"/>
<path d="M168.7 74h.5v.2h-.5z" fill-rule="evenodd"/>
<path d="M168.7 74.4h.5v.2h-.5z" fill-rule="evenodd"/>
<path d="M204.9 63.2h.2v.2h-.2z" fill-rule="evenodd"/>
<path d="M204.9 68.6h.2v.2h-.2z" fill-rule="evenodd"/>
<path d="M204.9 74.4h.5v.2h-.5z" fill-rule="evenodd"/>
<path d="M204.9 74h.2v.2h-.2z" fill-rule="evenodd"/>
<path d="M204.9 74h.2v.2h-.2z" fill-rule="evenodd"/>
<path d="M205.2 63.2h.2v.2h-.2z" fill-rule="evenodd"/>
<path d="M205.2 68.6h.2v.2h-.2z" fill-rule="evenodd"/>
<path d="M205.2 74h.2v.6h-.2z" fill-rule="evenodd"/>
<path d="M19.8 85.6h183.7v.5h-183.7z" fill-rule="evenodd"/>
<path d="M19.8 95h183.7v.5h-183.7z" fill-rule="evenodd"/>
<path d="M20 97.3h.2v.5h-.2z" fill-rule="evenodd"/>
<path d="M20 97.3h.5v.1h-.5z" fill-rule="evenodd"/>
<path d="M20.3 97.6h.2v.2h-.2z" fill-rule="evenodd"/>
<path d="M20.3 97.6h.2v.2h-.2z" fill-rule="evenodd"/>
<path d="M37.9 97.8h.3z" fill-rule="evenodd"/>
<path d="M37.9 97.3h.5v.1h-.5z" fill-rule="evenodd"/>
<path d="M37.9 97.6h.5v.2h-.5z" fill-rule="evenodd"/>
<path d="M88.8 97.8h.2z" fill-rule="evenodd"/>
<path d="M88.8 97.3h.5v.1h-.5z" fill-rule="evenodd"/>
<path d="M88.8 97.6h.5v.2h-.5z" fill-rule="evenodd"/>
<path d="M142.2 97.8h.2z" fill-rule="evenodd"/>
<path d="M142.2 97.3h.5v.1h-.5z" fill-rule="evenodd"/>
<path d="M142.2 97.6h.5v.2h-.5z" fill-rule="evenodd"/>
<path d="M157.4 97.8h.3z" fill-rule="evenodd"/>
<path d="M157.4 97.3h.5v.1h-.5z" fill-rule="evenodd"/>
<path d="M157.4 97.6h.5v.2h-.5z" fill-rule="evenodd"/>
<path d="M172.7 97.8h.2z" fill-rule="evenodd"/>
<path d="M172.7 97.3h.5v.1h-.5z" fill-rule="evenodd"/>
<path d="M172.7 97.6h.5v.2h-.5z" fill-rule="evenodd"/>
<path d="M188 97.8h.2z" fill-rule="evenodd"/>
<path d="M188 97.3h.5v.1h-.5z" fill-rule="evenodd"/>
<path d="M188 97.6h.5v.2h-.5z" fill-rule="evenodd"/>
<path d="M203.1 97.3h.5v.1h-.5z" fill-rule="evenodd"/>
<path d="M203.1 97.6h.1v.2h-.1z" fill-rule="evenodd"/>
<path d="M203.1 97.6h.1v.2h-.1z" fill-rule="evenodd"/>
<path d="M203.4 97.3h.2v.5h-.2z" fill-rule="evenodd"/>
<path d="M20 101.7h.2v.3h-.2z" fill-rule="evenodd"/>
<path d="M20 106.4h.2v.2h-.2z" fill-rule="evenodd"/>
<path d="M20 111h.2v.2h-.2z" fill-rule="evenodd"/>
<path d="M20 115.6h.2v.2h-.2z" fill-rule="evenodd"/>
<path d="M20.3 101.7h.2v.3h-.2z" fill-rule="evenodd"/>
<path d="M20.3 106.4h.2v.2h-.2z" fill-rule="evenodd"/>
<path d="M20.3 111h.2v.2h-.2z" fill-rule="evenodd"/>
<path d="M20.3 115.6h.2v.2h-.2z" fill-rule="evenodd"/>
<path d="M37.9 101.7h.3v.3h-.3z" fill-rule="evenodd"/>
<path d="M37.9 106.4h.3v.2h-.3z" fill-rule="evenodd"/>
<path d="M37.9 111h.3v.2h-.3z" fill-rule="evenodd"/>
<path d="M37.9 115.6h.3v.2h-.3z" fill-rule="evenodd"/>
<path d="M88.8 101.7h.2v.3h-.2z" fill-rule="evenodd"/>
<path d="M88.8 106.4h.2v.2h-.2z" fill-rule="evenodd"/>
<path d="M88.8 111h.2v.2h-.2z" fill-rule="evenodd"/>
<path d="M88.8 115.6h.2v.2h-.2z" fill-rule="evenodd"/>
<path d="M142.2 101.7h.2v.3h-.2z" fill-rule="evenodd"/>
<path d="M142.2 106.4h.2v.2h-.2z" fill-rule="evenodd"/>
<path d="M142.2 111h.2v.2h-.2z" fill-rule="evenodd"/>
<path d="M142.2 115.6h.2v.2h-.2z" fill-rule="evenodd"/>
<path d="M157.4 101.7h.3v.3h-.3z" fill-rule="evenodd"/>
<path d="M157.4 106.4h.3v.2h-.3z" fill-rule="evenodd"/>
<path d="M157.4 111h.3v.2h-.3z" fill-rule="evenodd"/>
<path d="M157.4 115.6h.3v.2h-.3z" fill-rule="evenodd"/>
<path d="M172.7 101.7h.2v.3h-.2z" fill-rule="evenodd"/>
<path d="M172.7 106.4h.2v.2h-.2z" fill-rule="evenodd"/>
<path d="M172.7 111h.2v.2h-.2z" fill-rule="evenodd"/>
<path d="M172.7 115.6h.2v.2h-.2z" fill-rule="evenodd"/>
<path d="M188 101.7h.2v.3h-.2z" fill-rule="evenodd"/>
<path d="M188 106.4h.2v.2h-.2z" fill-rule="evenodd"/>
<path d="M188 111h.2v.2h-.2z" fill-rule="evenodd"/>
<path d="M188 115.6h.2v.2h-.2z" fill-rule="evenodd"/>
<path d="M203.1 101.7h.1v.3h-.1z" fill-rule="evenodd"/>
<path d="M203.1 106.4h.1v.2h-.1z" fill-rule="evenodd"/>
<path d="M203.1 111h.1v.2h-.1z" fill-rule="evenodd"/>
<path d="M203.1 115.6h.1v.2h-.1z" fill-rule="evenodd"/>
<path d="M203.4 101.7h.2v.3h-.2z" fill-rule="evenodd"/>
<path d="M203.4 106.4h.2v.2h-.2z" fill-rule="evenodd"/>
<path d="M203.4 111h.2v.2h-.2z" fill-rule="evenodd"/>
<path d="M203.4 115.6h.2v.2h-.2z" fill-rule="evenodd"/>
<path d="M20 120.2h.2v.3h-.2z" fill-rule="evenodd"/>
<path d="M20 124.8h.2v.3h-.2z" fill-rule="evenodd"/>
<path d="M20 129.4h.2v.3h-.2z" fill-rule="evenodd"/>
<path d="M20 134.1h.2v.2h-.2z" fill-rule="evenodd"/>
<path d="M20 138.7h.2v.3h-.2z" fill-rule="evenodd"/>
<path d="M20.3 120.2h.2v.3h-.2z" fill-rule="evenodd"/>
<path d="M20.3 124.8h.2v.3h-.2z" fill-rule="evenodd"/>
<path d="M20.3 129.4h.2v.3h-.2z" fill-rule="evenodd"/>
<path d="M20.3 134.1h.2v.2h-.2z" fill-rule="evenodd"/>
<path d="M20.3 138.7h.2v.3h-.2z" fill-rule="evenodd"/>
<path d="M37.9 120.2h.3v.3h-.3z" fill-rule="evenodd"/>
<path d="M37.9 124.8h.3v.3h-.3z" fill-rule="evenodd"/>
<path d="M37.9 129.4h.3v.3h-.3z" fill-rule="evenodd"/>
<path d="M37.9 134.1h.3v.2h-.3z" fill-rule="evenodd"/>
<path d="M37.9 138.7h.3v.3h-.3z" fill-rule="evenodd"/>
<path d="M88.8 120.2h.2v.3h-.2z" fill-rule="evenodd"/>
<path d="M88.8 124.8h.2v.3h-.2z" fill-rule="evenodd"/>
<path d="M88.8 129.4h.2v.3h-.2z" fill-rule="evenodd"/>
<path d="M88.8 134.1h.2v.2h-.2z" fill-rule="evenodd"/>
<path d="M88.8 138.7h.2v.3h-.2z" fill-rule="evenodd"/>
<path d="M142.2 120.2h.2v.3h-.2z" fill-rule="evenodd"/>
<path d="M142.2 124.8h.2v.3h-.2z" fill-rule="evenodd"/>
<path d="M142.2 129.4h.2v.3h-.2z" fill-rule="evenodd"/>
<path d="M142.2 134.1h.2v.2h-.2z" fill-rule="evenodd"/>
<path d="M142.2 138.7h.2v.3h-.2z" fill-rule="evenodd"/>
<path d="M157.4 120.2h.3v.3h-.3z" fill-rule="evenodd"/>
<path d="M157.4 124.8h.3v.3h-.3z" fill-rule="evenodd"/>
<path d="M157.4 129.4h.3v.3h-.3z" fill-rule="evenodd"/>
<path d="M157.4 134.1h.3v.2h-.3z" fill-rule="evenodd"/>
<path d="M157.4 138.7h.3v.3h-.3z" fill-rule="evenodd"/>
<path d="M172.7 120.2h.2v.3h-.2z" fill-rule="evenodd"/>
<path d="M172.7 124.8h.2v.3h-.2z" fill-rule="evenodd"/>
<path d="M172.7 129.4h.2v.3h-.2z" fill-rule="evenodd"/>
<path d="M172.7 134.1h.2v.2h-.2z" fill-rule="evenodd"/>
<path d="M172.7 138.7h.2v.3h-.2z" fill-rule="evenodd"/>
<path d="M188 120.2h.2v.3h-.2z" fill-rule="evenodd"/>
<path d="M188 124.8h.2v.3h-.2z" fill-rule="evenodd"/>
<path d="M188 129.4h.2v.3h-.2z" fill-rule="evenodd"/>
<path d="M188 134.1h.2v.2h-.2z" fill-rule="evenodd"/>
<path d="M188 138.7h.2v.3h-.2z" fill-rule="evenodd"/>
<path d="M203.1 120.2h.1v.3h-.1z" fill-rule="evenodd"/>
<path d="M203.1 124.8h.1v.3h-.1z" fill-rule="evenodd"/>
<path d="M203.1 129.4h.1v.3h-.1z" fill-rule="evenodd"/>
<path d="M203.1 134.1h.1v.2h-.1z" fill-rule="evenodd"/>
<path d="M203.1 138.7h.1v.3h-.1z" fill-rule="evenodd"/>
<path d="M203.4 120.2h.2v.3h-.2z" fill-rule="evenodd"/>
<path d="M203.4 124.8h.2v.3h-.2z" fill-rule="evenodd"/>
<path d="M203.4 129.4h.2v.3h-.2z" fill-rule="evenodd"/>
<path d="M203.4 134.1h.2v.2h-.2z" fill-rule="evenodd"/>
<path d="M203.4 138.7h.2v.3h-.2z" fill-rule="evenodd"/>
<path d="M20 143.3h.2v.3h-.2z" fill-rule="evenodd"/>
<path d="M20 147.9h.2v.3h-.2z" fill-rule="evenodd"/>
<path d="M20 152.5h.2v.3h-.2z" fill-rule="evenodd"/>
<path d="M20 157.2h.2v.2h-.2z" fill-rule="evenodd"/>
<path d="M20.3 143.3h.2v.3h-.2z" fill-rule="evenodd"/>
<path d="M20.3 147.9h.2v.3h-.2z" fill-rule="evenodd"/>
<path d="M20.3 152.5h.2v.3h-.2z" fill-rule="evenodd"/>
<path d="M20.3 157.2h.2v.2h-.2z" fill-rule="evenodd"/>
<path d="M37.9 143.3h.3v.3h-.3z" fill-rule="evenodd"/>
<path d="M37.9 147.9h.3v.3h-.3z" fill-rule="evenodd"/>
<path d="M37.9 152.5h.3v.3h-.3z" fill-rule="evenodd"/>
<path d="M37.9 157.2h.3v.2h-.3z" fill-rule="evenodd"/>
<path d="M88.8 143.3h.2v.3h-.2z" fill-rule="evenodd"/>
<path d="M88.8 147.9h.2v.3h-.2z" fill-rule="evenodd"/>
<path d="M88.8 152.5h.2v.3h-.2z" fill-rule="evenodd"/>
<path d="M88.8 157.2h.2v.2h-.2z" fill-rule="evenodd"/>
<path d="M142.2 143.3h.2v.3h-.2z" fill-rule="evenodd"/>
<path d="M142.2 147.9h.2v.3h-.2z" fill-rule="evenodd"/>
<path d="M142.2 152.5h.2v.3h-.2z" fill-rule="evenodd"/>
<path d="M142.2 157.2h.2v.2h-.2z" fill-rule="evenodd"/>
<path d="M157.4 143.3h.3v.3h-.3z" fill-rule="evenodd"/>
<path d="M157.4 147.9h.3v.3h-.3z" fill-rule="evenodd"/>
<path d="M157.4 152.5h.3v.3h-.3z" fill-rule="evenodd"/>
<path d="M157.4 157.2h.3v.2h-.3z" fill-rule="evenodd"/>
<path d="M172.7 143.3h.2v.3h-.2z" fill-rule="evenodd"/>
<path d="M172.7 147.9h.2v.3h-.2z" fill-rule="evenodd"/>
<path d="M172.7 152.5h.2v.3h-.2z" fill-rule="evenodd"/>
<path d="M172.7 157.2h.2v.2h-.2z" fill-rule="evenodd"/>
<path d="M188 143.3h.2v.3h-.2z" fill-rule="evenodd"/>
<path d="M188 147.9h.2v.3h-.2z" fill-rule="evenodd"/>
<path d="M188 152.5h.2v.3h-.2z" fill-rule="evenodd"/>
<path d="M188 157.2h.2v.2h-.2z" fill-rule="evenodd"/>
<path d="M203.1 143.3h.1v.3h-.1z" fill-rule="evenodd"/>
<path d="M203.1 147.9h.1v.3h-.1z" fill-rule="evenodd"/>
<path d="M203.1 152.5h.1v.3h-.1z" fill-rule="evenodd"/>
<path d="M203.1 157.2h.1v.2h-.1z" fill-rule="evenodd"/>
<path d="M203.4 143.3h.2v.3h-.2z" fill-rule="evenodd"/>
<path d="M203.4 147.9h.2v.3h-.2z" fill-rule="evenodd"/>
<path d="M203.4 152.5h.2v.3h-.2z" fill-rule="evenodd"/>
<path d="M203.4 157.2h.2v.2h-.2z" fill-rule="evenodd"/>
<path d="M20 161.8h.2v.2h-.2z" fill-rule="evenodd"/>
<path d="M20 166.4h.2v.3h-.2z" fill-rule="evenodd"/>
<path d="M20 170.6h.2v.3h-.2z" fill-rule="evenodd"/>
<path d="M20 174.9h.2v.2h-.2z" fill-rule="evenodd"/>
<path d="M20 179.1h.2v.2h-.2z" fill-rule="evenodd"/>
<path d="M20.3 161.8h.2v.2h-.2z" fill-rule="evenodd"/>
<path d="M20.3 166.4h.2v.3h-.2z" fill-rule="evenodd"/>
<path d="M20.3 170.6h.2v.3h-.2z" fill-rule="evenodd"/>
<path d="M20.3 174.9h.2v.2h-.2z" fill-rule="evenodd"/>
<path d="M20.3 179.1h.2v.2h-.2z" fill-rule="evenodd"/>
<path d="M37.9 161.8h.3v.2h-.3z" fill-rule="evenodd"/>
<path d="M37.9 166.4h.3v.3h-.3z" fill-rule="evenodd"/>
<path d="M37.9 170.6h.3v.3h-.3z" fill-rule="evenodd"/>
<path d="M37.9 174.9h.3v.2h-.3z" fill-rule="evenodd"/>
<path d="M37.9 179.1h.3v.2h-.3z" fill-rule="evenodd"/>
<path d="M88.8 161.8h.2v.2h-.2z" fill-rule="evenodd"/>
<path d="M88.8 166.4h.2v.3h-.2z" fill-rule="evenodd"/>
<path d="M88.8 170.6h.2v.3h-.2z" fill-rule="evenodd"/>
<path d="M88.8 174.9h.2v.2h-.2z" fill-rule="evenodd"/>
<path d="M88.8 179.1h.2v.2h-.2z" fill-rule="evenodd"/>
<path d="M142.2 161.8h.2v.2h-.2z" fill-rule="evenodd"/>
<path d="M142.2 166.4h.2v.3h-.2z" fill-rule="evenodd"/>
<path d="M142.2 170.6h.2v.3h-.2z" fill-rule="evenodd"/>
<path d="M142.2 174.9h.2v.2h-.2z" fill-rule="evenodd"/>
<path d="M142.2 179.1h.2v.2h-.2z" fill-rule="evenodd"/>
<path d="M157.4 161.8h.3v.2h-.3z" fill-rule="evenodd"/>
<path d="M157.4 166.4h.3v.3h-.3z" fill-rule="evenodd"/>
<path d="M157.4 170.6h.3v.3h-.3z" fill-rule="evenodd"/>
<path d="M157.4 174.9h.3v.2h-.3z" fill-rule="evenodd"/>
<path d="M157.4 179.1h.3v.2h-.3z" fill-rule="evenodd"/>
<path d="M172.7 161.8h.2v.2h-.2z" fill-rule="evenodd"/>
<path d="M172.7 166.4h.2v.3h-.2z" fill-rule="evenodd"/>
<path d="M172.7 170.6h.2v.3h-.2z" fill-rule="evenodd"/>
<path d="M172.7 174.9h.2v.2h-.2z" fill-rule="evenodd"/>
<path d="M172.7 179.1h.2v.2h-.2z" fill-rule="evenodd"/>
<path d="M188 161.8h.2v.2h-.2z" fill-rule="evenodd"/>
<path d="M188 166.4h.2v.3h-.2z" fill-rule="evenodd"/>
<path d="M188 170.6h.2v.3h-.2z" fill-rule="evenodd"/>
<path d="M188 174.9h.2v.2h-.2z" fill-rule="evenodd"/>
<path d="M188 179.1h.2v.2h-.2z" fill-rule="evenodd"/>
<path d="M203.1 161.8h.1v.2h-.1z" fill-rule="evenodd"/>
<path d="M203.1 166.4h.1v.3h-.1z" fill-rule="evenodd"/>
<path d="M203.1 170.6h.1v.3h-.1z" fill-rule="evenodd"/>
<path d="M203.1 174.9h.1v.2h-.1z" fill-rule="evenodd"/>
<path d="M203.1 179.1h.1v.2h-.1z" fill-rule="evenodd"/>
<path d="M203.4 161.8h.2v.2h-.2z" fill-rule="evenodd"/>
<path d="M203.4 166.4h.2v.3h-.2z" fill-rule="evenodd"/>
<path d="M203.4 170.6h.2v.3h-.2z" fill-rule="evenodd"/>
<path d="M203.4 174.9h.2v.2h-.2z" fill-rule="evenodd"/>
<path d="M203.4 179.1h.2v.2h-.2z" fill-rule="evenodd"/>
<path d="M20 183.3h.2v.2h-.2z" fill-rule="evenodd"/>
<path d="M20 187.5h.2v.3h-.2z" fill-rule="evenodd"/>
<path d="M20 191.7h.2v.3h-.2z" fill-rule="evenodd"/>
<path d="M20 195.9h.2v.3h-.2z" fill-rule="evenodd"/>
<path d="M20.3 183.3h.2v.2h-.2z" fill-rule="evenodd"/>
<path d="M20.3 187.5h.2v.3h-.2z" fill-rule="evenodd"/>
<path d="M20.3 191.7h.2v.3h-.2z" fill-rule="evenodd"/>
<path d="M20.3 195.9h.2v.3h-.2z" fill-rule="evenodd"/>
<path d="M37.9 183.3h.3v.2h-.3z" fill-rule="evenodd"/>
<path d="M37.9 187.5h.3v.3h-.3z" fill-rule="evenodd"/>
<path d="M37.9 191.7h.3v.3h-.3z" fill-rule="evenodd"/>
<path d="M37.9 195.9h.3v.3h-.3z" fill-rule="evenodd"/>
<path d="M88.8 183.3h.2v.2h-.2z" fill-rule="evenodd"/>
<path d="M88.8 187.5h.2v.3h-.2z" fill-rule="evenodd"/>
<path d="M88.8 191.7h.2v.3h-.2z" fill-rule="evenodd"/>
<path d="M88.8 195.9h.2v.3h-.2z" fill-rule="evenodd"/>
<path d="M142.2 183.3h.2v.2h-.2z" fill-rule="evenodd"/>
<path d="M142.2 187.5h.2v.3h-.2z" fill-rule="evenodd"/>
<path d="M142.2 191.7h.2v.3h-.2z" fill-rule="evenodd"/>
<path d="M142.2 195.9h.2v.3h-.2z" fill-rule="evenodd"/>
<path d="M157.4 183.3h.3v.2h-.3z" fill-rule="evenodd"/>
<path d="M157.4 187.5h.3v.3h-.3z" fill-rule="evenodd"/>
<path d="M157.4 191.7h.3v.3h-.3z" fill-rule="evenodd"/>
<path d="M157.4 195.9h.3v.3h-.3z" fill-rule="evenodd"/>
<path d="M172.7 183.3h.2v.2h-.2z" fill-rule="evenodd"/>
<path d="M172.7 187.5h.2v.3h-.2z" fill-rule="evenodd"/>
<path d="M172.7 191.7h.2v.3h-.2z" fill-rule="evenodd"/>
<path d="M172.7 195.9h.2v.3h-.2z" fill-rule="evenodd"/>
<path d="M188 183.3h.2v.2h-.2z" fill-rule="evenodd"/>
<path d="M188 187.5h.2v.3h-.2z" fill-rule="evenodd"/>
<path d="M188 191.7h.2v.3h-.2z" fill-rule="evenodd"/>
<path d="M188 195.9h.2v.3h-.2z" fill-rule="evenodd"/>
<path d="M203.1 183.3h.1v.2h-.1z" fill-rule="evenodd"/>
<path d="M203.1 187.5h.1v.3h-.1z" fill-rule="evenodd"/>
<path d="M203.1 191.7h.1v.3h-.1z" fill-rule="evenodd"/>
<path d="M203.1 195.9h.1v.3h-.1z" fill-rule="evenodd"/>
<path d="M203.4 183.3h.2v.2h-.2z" fill-rule="evenodd"/>
<path d="M203.4 187.5h.2v.3h-.2z" fill-rule="evenodd"/>
<path d="M203.4 191.7h.2v.3h-.2z" fill-rule="evenodd"/>
<path d="M203.4 195.9h.2v.3h-.2z" fill-rule="evenodd"/>
<path d="M20 200.6h.2v.2h-.2z" fill-rule="evenodd"/>
<path d="M20 205.2h.2v.2h-.2z" fill-rule="evenodd"/>
<path d="M20 209.7h.2v.3h-.2z" fill-rule="evenodd"/>
<path d="M20 214.3h.2v.3h-.2z" fill-rule="evenodd"/>
<path d="M20 218.9h.2v.3h-.2z" fill-rule="evenodd"/>
<path d="M20.3 200.6h.2v.2h-.2z" fill-rule="evenodd"/>
<path d="M20.3 205.2h.2v.2h-.2z" fill-rule="evenodd"/>
<path d="M20.3 209.7h.2v.3h-.2z" fill-rule="evenodd"/>
<path d="M20.3 214.3h.2v.3h-.2z" fill-rule="evenodd"/>
<path d="M20.3 218.9h.2v.3h-.2z" fill-rule="evenodd"/>
<path d="M37.9 200.6h.3v.2h-.3z" fill-rule="evenodd"/>
<path d="M37.9 205.2h.3v.2h-.3z" fill-rule="evenodd"/>
<path d="M37.9 209.7h.3v.3h-.3z" fill-rule="evenodd"/>
<path d="M37.9 214.3h.3v.3h-.3z" fill-rule="evenodd"/>
<path d="M37.9 218.9h.3v.3h-.3z" fill-rule="evenodd"/>
<path d="M88.8 200.6h.2v.2h-.2z" fill-rule="evenodd"/>
<path d="M88.8 205.2h.2v.2h-.2z" fill-rule="evenodd"/>
<path d="M88.8 209.7h.2v.3h-.2z" fill-rule="evenodd"/>
<path d="M88.8 214.3h.2v.3h-.2z" fill-rule="evenodd"/>
<path d="M88.8 218.9h.2v.3h-.2z" fill-rule="evenodd"/>
<path d="M142.2 200.6h.2v.2h-.2z" fill-rule="evenodd"/>
<path d="M142.2 205.2h.2v.2h-.2z" fill-rule="evenodd"/>
<path d="M142.2 209.7h.2v.3h-.2z" fill-rule="evenodd"/>
<path d="M142.2 214.3h.2v.3h-.2z" fill-rule="evenodd"/>
<path d="M142.2 218.9h.2v.3h-.2z" fill-rule="evenodd"/>
<path d="M157.4 200.6h.3v.2h-.3z" fill-rule="evenodd"/>
<path d="M157.4 205.2h.3v.2h-.3z" fill-rule="evenodd"/>
<path d="M157.4 209.7h.3v.3h-.3z" fill-rule="evenodd"/>
<path d="M157.4 214.3h.3v.3h-.3z" fill-rule="evenodd"/>
<path d="M157.4 218.9h.3v.3h-.3z" fill-rule="evenodd"/>
<path d="M172.7 200.6h.2v.2h-.2z" fill-rule="evenodd"/>
<path d="M172.7 205.2h.2v.2h-.2z" fill-rule="evenodd"/>
<path d="M172.7 209.7h.2v.3h-.2z" fill-rule="evenodd"/>
<path d="M172.7 214.3h.2v.3h-.2z" fill-rule="evenodd"/>
<path d="M172.7 218.9h.2v.3h-.2z" fill-rule="evenodd"/>
<path d="M188 200.6h.2v.2h-.2z" fill-rule="evenodd"/>
<path d="M188 205.2h.2v.2h-.2z" fill-rule="evenodd"/>
<path d="M188 209.7h.2v.3h-.2z" fill-rule="evenodd"/>
<path d="M188 214.3h.2v.3h-.2z" fill-rule="evenodd"/>
<path d="M188 218.9h.2v.3h-.2z" fill-rule="evenodd"/>
<path d="M203.1 200.6h.1v.2h-.1z" fill-rule="evenodd"/>
<path d="M203.1 205.2h.1v.2h-.1z" fill-rule="evenodd"/>
<path d="M203.1 209.7h.1v.3h-.1z" fill-rule="evenodd"/>
<path d="M203.1 214.3h.1v.3h-.1z" fill-rule="evenodd"/>
<path d="M203.1 218.9h.1v.3h-.1z" fill-rule="evenodd"/>
<path d="M203.4 200.6h.2v.2h-.2z" fill-rule="evenodd"/>
<path d="M203.4 205.2h.2v.2h-.2z" fill-rule="evenodd"/>
<path d="M203.4 209.7h.2v.3h-.2z" fill-rule="evenodd"/>
<path d="M203.4 214.3h.2v.3h-.2z" fill-rule="evenodd"/>
<path d="M203.4 218.9h.2v.3h-.2z" fill-rule="evenodd"/>
<path d="M20 223.6h.2v.3h-.2z" fill-rule="evenodd"/>
<path d="M20 228.2h.2v.5h-.2z" fill-rule="evenodd"/>
<path d="M20 228.6h.5v.1h-.5z" fill-rule="evenodd"/>
<path d="M20.3 223.6h.2v.3h-.2z" fill-rule="evenodd"/>
<path d="M20.3 228.2h.2v.2h-.2z" fill-rule="evenodd"/>
<path d="M20.3 228.2h.2v.2h-.2z" fill-rule="evenodd"/>
<path d="M37.9 223.6h.3v.3h-.3z" fill-rule="evenodd"/>
<path d="M37.9 228.2h.5v.2h-.5z" fill-rule="evenodd"/>
<path d="M37.9 228.6h.5v.1h-.5z" fill-rule="evenodd"/>
<path d="M88.8 223.6h.2v.3h-.2z" fill-rule="evenodd"/>
<path d="M88.8 228.2h.5v.2h-.5z" fill-rule="evenodd"/>
<path d="M88.8 228.6h.5v.1h-.5z" fill-rule="evenodd"/>
<path d="M142.2 223.6h.2v.3h-.2z" fill-rule="evenodd"/>
<path d="M142.2 228.2h.5v.2h-.5z" fill-rule="evenodd"/>
<path d="M142.2 228.6h.5v.1h-.5z" fill-rule="evenodd"/>
<path d="M157.4 223.6h.3v.3h-.3z" fill-rule="evenodd"/>
<path d="M157.4 228.2h.5v.2h-.5z" fill-rule="evenodd"/>
<path d="M157.4 228.6h.5v.1h-.5z" fill-rule="evenodd"/>
<path d="M172.7 223.6h.2v.3h-.2z" fill-rule="evenodd"/>
<path d="M172.7 228.2h.5v.2h-.5z" fill-rule="evenodd"/>
<path d="M172.7 228.6h.5v.1h-.5z" fill-rule="evenodd"/>
<path d="M188 223.6h.2v.3h-.2z" fill-rule="evenodd"/>
<path d="M188 228.2h.5v.2h-.5z" fill-rule="evenodd"/>
<path d="M188 228.6h.5v.1h-.5z" fill-rule="evenodd"/>
<path d="M203.1 223.6h.1v.3h-.1z" fill-rule="evenodd"/>
<path d="M203.1 228.6h.5v.1h-.5z" fill-rule="evenodd"/>
<path d="M203.1 228.2h.1v.2h-.1z" fill-rule="evenodd"/>
<path d="M203.1 228.2h.1v.2h-.1z" fill-rule="evenodd"/>
<path d="M203.4 223.6h.2v.3h-.2z" fill-rule="evenodd"/>
<path d="M203.4 228.2h.2v.5h-.2z" fill-rule="evenodd"/>
</g>
<g fill="none" stroke="#000" stroke-width=".2">
<path d="M20.2 36.4v5.1M20.5 36.4v5.1M20.6 35.9h55.1M20.6 36.3h55.1M76.2 35.9h31.4M76.2 36.3h31.4M107.7 36.4v5.1M108 36.4v5.1M114.4 36.4v5.1M114.7 36.4v5.1M114.8 35.9h53.9M114.8 36.3h53.9"/>
<path d="M169.2 35.9h35.7M169.2 36.3h35.7M205 36.4v5.1M205.3 36.4v5.1M20.2 41.8v5.1M20.2 47.2v5.1M20.2 52.6v5.1M20.2 58v5.1M20.5 41.8v5.1M20.5 47.2v5.1M20.5 52.6v5.1M20.5 58v5.1"/>
<path d="M107.7 41.8v5.1M107.7 47.2v5.1M107.7 52.6v5.1M107.7 58v5.1M108 41.8v5.1M108 47.2v5.1M108 52.6v5.1M108 58v5.1M114.4 41.8v5.2M114.4 47.2v5.2M114.4 52.6v5.2M114.4 58v5.2"/>
<path d="M114.7 41.8v5.2M114.7 47.2v5.2M114.7 52.6v5.2M114.7 58v5.2M205 41.8v5.2M205 47.2v5.2M205 52.6v5.2M205 58v5.2M205.3 41.8v5.2M205.3 47.2v5.2M205.3 52.6v5.2M205.3 58v5.2"/>
<path d="M20.2 63.4v5.1M20.2 68.8v5.1M20.5 63.4v5.1M20.5 68.8v5.1M20.6 74.3h55.1M20.6 74h55.1M76.2 74.3h31.4M76.2 74h31.4M107.7 63.4v5.1M107.7 68.8v5.1M108 63.4v5.1M108 68.8v5.1"/>
<path d="M114.4 63.4v5.2M114.4 68.8v5.2M114.7 63.4v5.2M114.7 68.8v5.2M114.8 74.5h53.9M114.8 74.1h53.9M169.2 74.5h35.7M169.2 74.1h35.7M205 63.4v5.2M205 68.8v5.2M205.3 63.4v5.2M205.3 68.8v5.2"/>
<path d="M20.1 97.8v3.9M20.4 97.8v3.9M20.5 97.3h17.4M20.5 97.7h17.4M38.4 97.3h50.4M38.4 97.7h50.4M89.3 97.3h52.9M89.3 97.7h52.9M142.7 97.3h14.7M142.7 97.7h14.7M157.9 97.3h14.8M157.9 97.7h14.8"/>
<path d="M173.2 97.3h14.8M173.2 97.7h14.8M188.5 97.3h14.6M188.5 97.7h14.6M203.2 97.8v3.9M203.5 97.8v3.9M20.1 102v4.4M20.1 106.6v4.4M20.1 111.2v4.4M20.1 115.8v4.4M20.4 102v4.4M20.4 106.6v4.4"/>
<path d="M20.4 111.2v4.4M20.4 115.8v4.4M203.2 102v4.4M203.2 106.6v4.4M203.2 111.2v4.4M203.2 115.8v4.4M203.5 102v4.4M203.5 106.6v4.4M203.5 111.2v4.4M203.5 115.8v4.4M20.1 120.5v4.3M20.1 125.1v4.3"/>
<path d="M20.1 129.7v4.4M20.1 134.3v4.4M20.1 139v4.3M20.4 120.5v4.3M20.4 125.1v4.3M20.4 129.7v4.4M20.4 134.3v4.4M20.4 139v4.3M203.2 120.5v4.3M203.2 125.1v4.3M203.2 129.7v4.4M203.2 134.3v4.4"/>
<path d="M203.2 139v4.3M203.5 120.5v4.3M203.5 125.1v4.3M203.5 129.7v4.4M203.5 134.3v4.4M203.5 139v4.3M20.1 143.6v4.3M20.1 148.2v4.3M20.1 152.8v4.4M20.1 157.4v4.4M20.4 143.6v4.3M20.4 148.2v4.3"/>
<path d="M20.4 152.8v4.4M20.4 157.4v4.4M203.2 143.6v4.3M203.2 148.2v4.3M203.2 152.8v4.4M203.2 157.4v4.4M203.5 143.6v4.3M203.5 148.2v4.3M203.5 152.8v4.4M203.5 157.4v4.4M20.1 162v4.4M20.1 166.7v3.9"/>
<path d="M20.1 170.9v4M20.1 175.1v4M20.1 179.3v4M20.4 162v4.4M20.4 166.7v3.9M20.4 170.9v4M20.4 175.1v4M20.4 179.3v4M203.2 162v4.4M203.2 166.7v3.9M203.2 170.9v4M203.2 175.1v4"/>
<path d="M203.2 179.3v4M203.5 162v4.4M203.5 166.7v3.9M203.5 170.9v4M203.5 175.1v4M203.5 179.3v4M20.1 183.5v4M20.1 187.8v3.9M20.1 192v3.9M20.1 196.2v4.4M20.4 183.5v4M20.4 187.8v3.9"/>
<path d="M20.4 192v3.9M20.4 196.2v4.4M203.2 183.5v4M203.2 187.8v3.9M203.2 192v3.9M203.2 196.2v4.4M203.5 183.5v4M203.5 187.8v3.9M203.5 192v3.9M203.5 196.2v4.4M20.1 200.8v4.4M20.1 205.4v4.3"/>
<path d="M20.1 210v4.3M20.1 214.6v4.3M20.1 219.2v4.4M20.4 200.8v4.4M20.4 205.4v4.3M20.4 210v4.3M20.4 214.6v4.3M20.4 219.2v4.4M203.2 200.8v4.4M203.2 205.4v4.3M203.2 210v4.3M203.2 214.6v4.3"/>
<path d="M203.2 219.2v4.4M203.5 200.8v4.4M203.5 205.4v4.3M203.5 210v4.3M203.5 214.6v4.3M203.5 219.2v4.4M20.1 223.9v4.3M20.4 223.9v4.3M20.5 228.6h17.4M20.5 228.3h17.4M38.4 228.6h50.4M38.4 228.3h50.4"/>
<path d="M89.3 228.6h52.9M89.3 228.3h52.9M142.7 228.6h14.7M142.7 228.3h14.7M157.9 228.6h14.8M157.9 228.3h14.8M173.2 228.6h14.8M173.2 228.3h14.8M188.5 228.6h14.6M188.5 228.3h14.6M203.2 223.9v4.3M203.5 223.9v4.3"/>
</g>
<g fill="none" stroke="#000" stroke-width=".25">
<path d="M75.8 36.4v5.1M168.9 36.4v5.1M20.6 41.7h55.1M20.6 47h55.1M20.6 52.5h55.1M20.6 57.8h55.1M75.8 41.8v5.1M75.8 47.2v5.1M75.8 52.6v5.1M75.8 58v5.1M75.9 41.7h31.7M75.9 47h31.7"/>
<path d="M75.9 52.5h31.7M75.9 57.8h31.7M114.8 41.7h53.9M114.8 52.5h53.9M114.8 47.1h53.9M114.8 57.9h53.9M168.9 41.8v5.2M168.9 47.2v5.2M168.9 52.6v5.2M168.9 58v5.2M169 41.7h35.9M169 52.5h35.9"/>
<path d="M169 47.1h35.9M169 57.9h35.9M20.6 63.3h55.1M20.6 68.6h55.1M75.8 63.4v5.1M75.8 68.8v5.1M75.9 63.3h31.7M75.9 68.6h31.7M114.8 63.3h53.9M114.8 68.7h53.9M168.9 63.4v5.2M168.9 68.8v5.2"/>
<path d="M169 63.3h35.9M169 68.7h35.9M38.1 97.8v3.9M88.9 97.8v3.9M142.3 97.8v3.9M157.5 97.8v3.9M172.8 97.8v3.9M188.1 97.8v3.9M20.5 101.8h17.4M20.5 106.5h17.4M20.5 111.1h17.4M38.1 102v4.4"/>
<path d="M38.1 106.6v4.4M38.1 111.2v4.4M38.1 115.8v4.4M38.2 101.8h50.6M38.2 106.5h50.6M38.2 111.1h50.6M88.9 102v4.4M88.9 106.6v4.4M88.9 111.2v4.4M88.9 115.8v4.4M89 101.8h53.2M89 106.5h53.2"/>
<path d="M89 111.1h53.2M89 115.7h53.2M142.3 102v4.4M142.3 106.6v4.4M142.3 111.2v4.4M142.3 115.8v4.4M142.4 101.8h15M142.4 106.5h15M142.4 111.1h15M142.4 115.7h15M157.5 102v4.4M157.5 106.6v4.4"/>
<path d="M157.5 111.2v4.4M157.5 115.8v4.4M157.7 101.8h15M157.7 106.5h15M157.7 111.1h15M157.7 115.7h15M172.8 102v4.4M172.8 106.6v4.4M172.8 111.2v4.4M172.8 115.8v4.4M172.9 101.8h15.1M172.9 106.5h15.1"/>
<path d="M172.9 111.1h15.1M172.9 115.7h15.1M188.1 102v4.4M188.1 106.6v4.4M188.1 111.2v4.4M188.1 115.8v4.4M188.2 101.8h14.9M188.2 106.5h14.9M188.2 111.1h14.9M188.2 115.7h14.9M20.5 120.3h17.4M20.5 129.6h17.4"/>
<path d="M20.5 134.2h17.4M20.5 138.8h17.4M38.1 120.5v4.3M38.1 125.1v4.3M38.1 129.7v4.4M38.1 134.3v4.4M38.1 139v4.3M38.2 120.3h50.6M38.2 129.6h50.6M38.2 134.2h50.6M38.2 138.8h50.6M88.9 120.5v4.3"/>
<path d="M88.9 125.1v4.3M88.9 129.7v4.4M88.9 134.3v4.4M88.9 139v4.3M89 120.3h53.2M89 124.9h53.2M89 129.6h53.2M89 134.2h53.2M89 138.8h53.2M142.3 120.5v4.3M142.3 125.1v4.3M142.3 129.7v4.4"/>
<path d="M142.3 134.3v4.4M142.3 139v4.3M142.4 120.3h15M142.4 124.9h15M142.4 129.6h15M142.4 134.2h15M142.4 138.8h15M157.5 120.5v4.3M157.5 125.1v4.3M157.5 129.7v4.4M157.5 134.3v4.4M157.5 139v4.3"/>
<path d="M157.7 120.3h15M157.7 124.9h15M157.7 129.6h15M157.7 134.2h15M157.7 138.8h15M172.8 120.5v4.3M172.8 125.1v4.3M172.8 129.7v4.4M172.8 134.3v4.4M172.8 139v4.3M172.9 120.3h15.1M172.9 124.9h15.1"/>
<path d="M172.9 129.6h15.1M172.9 134.2h15.1M172.9 138.8h15.1M188.1 120.5v4.3M188.1 125.1v4.3M188.1 129.7v4.4M188.1 134.3v4.4M188.1 139v4.3M188.2 120.3h14.9M188.2 124.9h14.9M188.2 129.6h14.9M188.2 134.2h14.9"/>
<path d="M188.2 138.8h14.9M20.5 148.1h17.4M20.5 157.3h17.4M38.1 143.6v4.3M38.1 148.2v4.3M38.1 152.8v4.4M38.1 157.4v4.4M38.2 148.1h50.6M38.2 157.3h50.6M88.9 143.6v4.3M88.9 148.2v4.3M88.9 152.8v4.4"/>
<path d="M88.9 157.4v4.4M89 143.4h53.2M89 148.1h53.2M89 152.7h53.2M89 157.3h53.2M142.3 143.6v4.3M142.3 148.2v4.3M142.3 152.8v4.4M142.3 157.4v4.4M142.4 143.4h15M142.4 148.1h15M142.4 152.7h15"/>
<path d="M142.4 157.3h15M157.5 143.6v4.3M157.5 148.2v4.3M157.5 152.8v4.4M157.5 157.4v4.4M157.7 143.4h15M157.7 148.1h15M157.7 152.7h15M157.7 157.3h15M172.8 143.6v4.3M172.8 148.2v4.3M172.8 152.8v4.4"/>
<path d="M172.8 157.4v4.4M172.9 143.4h15.1M172.9 148.1h15.1M172.9 152.7h15.1M172.9 157.3h15.1M188.1 143.6v4.3M188.1 148.2v4.3M188.1 152.8v4.4M188.1 157.4v4.4M188.2 143.4h14.9M188.2 148.1h14.9M188.2 152.7h14.9"/>
<path d="M188.2 157.3h14.9M20.5 161.9h17.4M20.5 166.6h17.4M20.5 170.8h17.4M38.1 162v4.4M38.1 170.9v4M38.1 175.1v4M38.1 179.3v4M38.2 161.9h50.6M38.2 166.6h50.6M38.2 170.8h50.6M88.9 162v4.4"/>
<path d="M88.9 170.9v4M88.9 175.1v4M88.9 179.3v4M89 161.9h53.2M89 166.6h53.2M89 170.8h53.2M89 175h53.2M89 179.2h53.2M142.3 162v4.4M142.3 170.9v4M142.3 175.1v4M142.3 179.3v4"/>
<path d="M142.4 161.9h15M142.4 166.6h15M142.4 170.8h15M142.4 175h15M142.4 179.2h15M157.5 162v4.4M157.5 170.9v4M157.5 175.1v4M157.5 179.3v4M157.7 161.9h15M157.7 166.6h15M157.7 170.8h15"/>
<path d="M157.7 175h15M157.7 179.2h15M172.8 162v4.4M172.8 170.9v4M172.8 175.1v4M172.8 179.3v4M172.9 161.9h15.1M172.9 166.6h15.1M172.9 170.8h15.1M172.9 175h15.1M172.9 179.2h15.1M188.1 162v4.4"/>
<path d="M188.1 170.9v4M188.1 175.1v4M188.1 179.3v4M188.2 161.9h14.9M188.2 166.6h14.9M188.2 170.8h14.9M188.2 175h14.9M188.2 179.2h14.9M20.5 196.1h17.4M38.1 183.5v4M38.1 187.8v3.9M38.1 192v3.9"/>
<path d="M38.1 196.2v4.4M38.2 196.1h50.6M88.9 183.5v4M88.9 187.8v3.9M88.9 192v3.9M88.9 196.2v4.4M89 183.4h53.2M89 187.6h53.2M89 191.8h53.2M89 196.1h53.2M142.3 183.5v4M142.3 187.8v3.9"/>
<path d="M142.3 192v3.9M142.3 196.2v4.4M142.4 183.4h15M142.4 187.6h15M142.4 191.8h15M142.4 196.1h15M157.5 183.5v4M157.5 187.8v3.9M157.5 192v3.9M157.5 196.2v4.4M157.7 183.4h15M157.7 187.6h15"/>
<path d="M157.7 191.8h15M157.7 196.1h15M172.8 183.5v4M172.8 187.8v3.9M172.8 192v3.9M172.8 196.2v4.4M172.9 183.4h15.1M172.9 187.6h15.1M172.9 191.8h15.1M172.9 196.1h15.1M188.1 183.5v4M188.1 187.8v3.9"/>
<path d="M188.1 192v3.9M188.1 196.2v4.4M188.2 183.4h14.9M188.2 187.6h14.9M188.2 191.8h14.9M188.2 196.1h14.9M20.5 200.7h17.4M20.5 205.3h17.4M20.5 209.8h17.4M20.5 214.4h17.4M20.5 219.1h17.4M38.1 200.8v4.4"/>
<path d="M38.1 210v4.3M38.1 214.6v4.3M38.1 219.2v4.4M38.2 200.7h50.6M38.2 205.3h50.6M38.2 209.8h50.6M38.2 214.4h50.6M38.2 219.1h50.6M88.9 200.8v4.4M88.9 210v4.3M88.9 214.6v4.3M88.9 219.2v4.4"/>
<path d="M89 200.7h53.2M89 205.3h53.2M89 209.8h53.2M89 214.4h53.2M89 219.1h53.2M142.3 200.8v4.4M142.3 210v4.3M142.3 214.6v4.3M142.3 219.2v4.4M142.4 200.7h15M142.4 205.3h15M142.4 209.8h15"/>
<path d="M142.4 214.4h15M142.4 219.1h15M157.5 200.8v4.4M157.5 210v4.3M157.5 214.6v4.3M157.5 219.2v4.4M157.7 200.7h15M157.7 205.3h15M157.7 209.8h15M157.7 214.4h15M157.7 219.1h15M172.8 200.8v4.4"/>
<path d="M172.8 210v4.3M172.8 214.6v4.3M172.8 219.2v4.4M172.9 200.7h15.1M172.9 205.3h15.1M172.9 209.8h15.1M172.9 214.4h15.1M172.9 219.1h15.1M188.1 200.8v4.4M188.1 210v4.3M188.1 214.6v4.3M188.1 219.2v4.4"/>
<path d="M188.2 200.7h14.9M188.2 205.3h14.9M188.2 209.8h14.9M188.2 214.4h14.9M188.2 219.1h14.9M20.5 223.7h17.4M38.1 223.9v4.3M38.2 223.7h50.6M88.9 223.9v4.3M89 223.7h53.2M142.3 223.9v4.3M142.4 223.7h15"/>
<path d="M157.5 223.9v4.3M157.7 223.7h15M172.8 223.9v4.3M172.9 223.7h15.1M188.1 223.9v4.3M188.2 223.7h14.9"/>
</g>
<use href="#words"/>
</svg>
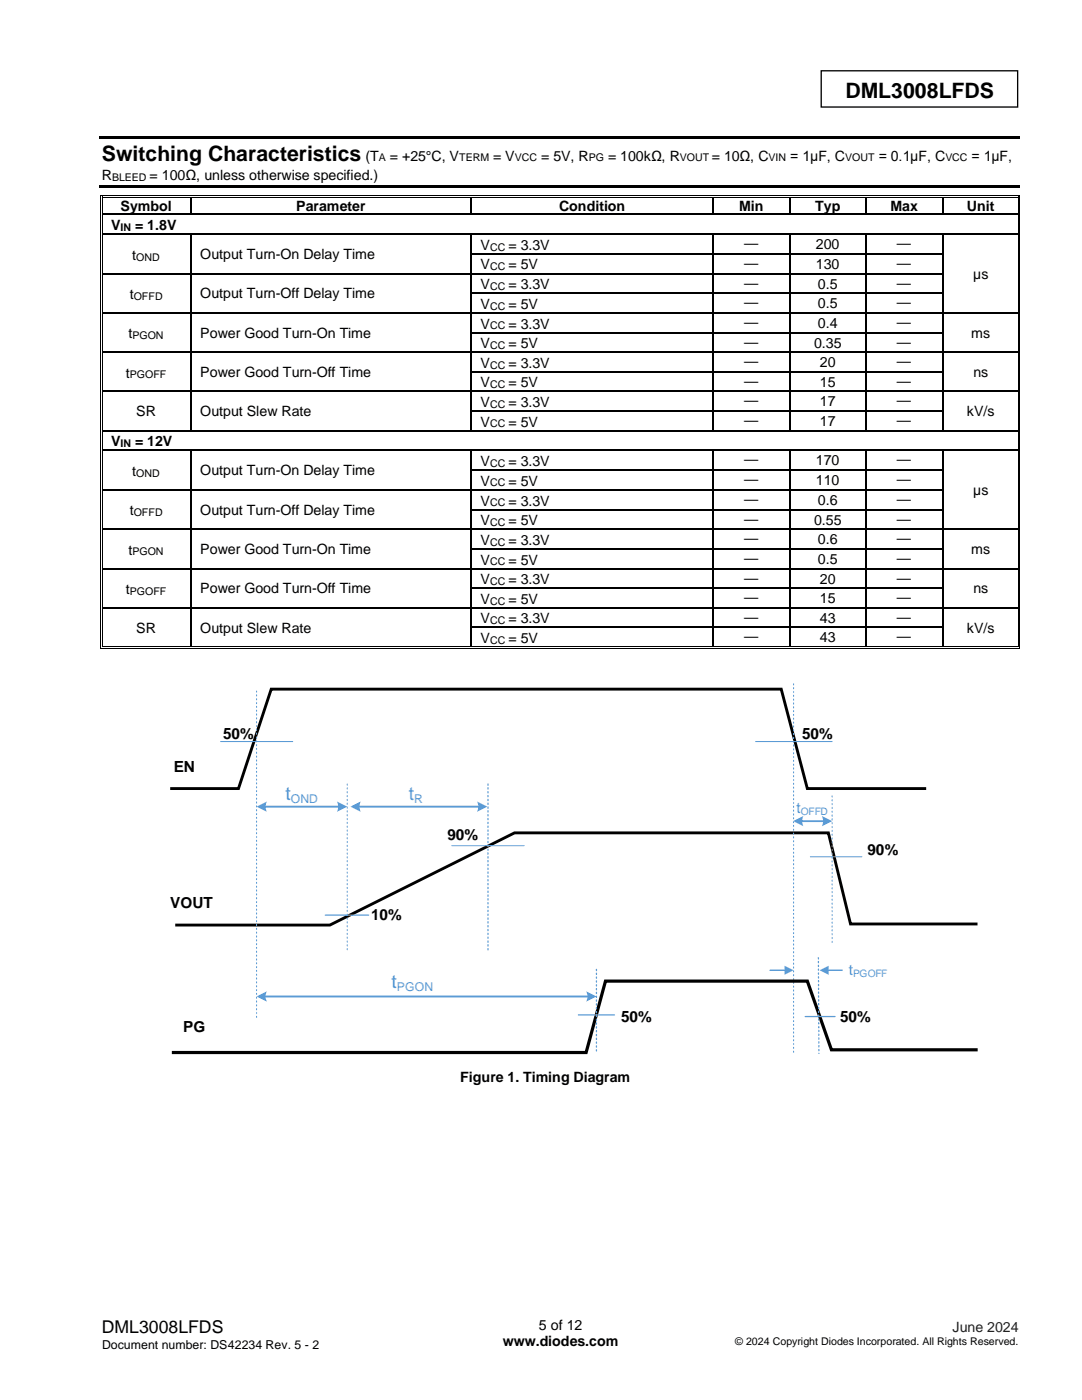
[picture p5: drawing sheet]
<svg xmlns="http://www.w3.org/2000/svg" width="216mm" height="279mm" viewBox="0 0 216 279" stroke-linecap="round" stroke-linejoin="round" font-family="sans-serif">
<defs><g id="words">
<g font-size="4.2">
<text x="168.7" y="19.5">DML3008LFDS</text>
<text x="182.3" y="24.4">6</text>
<text x="20.3" y="32.1">Switching Characteristics</text>
</g>
<g font-size="3.8" fill="#5b9bd5">
<text x="57" y="159.6">t</text>
<text x="81.5" y="159.6">t</text>
<text x="78.1" y="197.2">t</text>
</g>
<text font-size="3.5" x="20.3" y="266.1">DML3008LFDS</text>
<g font-size="3.1">
<text x="44.6" y="147.5">50%</text>
<text x="160.1" y="147.5">50%</text>
<text x="34.7" y="154">EN</text>
<text x="89.3" y="167.7">90%</text>
<text x="173.1" y="170.6">90%</text>
<text x="34" y="181.3">VOUT</text>
<text x="74.1" y="183.6">10%</text>
<text x="124" y="204">50%</text>
<text x="167.6" y="204">50%</text>
<text x="36.6" y="206">PG</text>
</g>
<g font-size="3.1" fill="#5b9bd5">
<text x="159" y="162.3">t</text>
<text x="169.4" y="194.7">t</text>
</g>
<g font-size="2.8">
<text x="20.3" y="35.9">R</text>
<text x="29.9" y="35.9">= 100Ω, unless otherwise specified.)</text>
<text x="72.9" y="32.1">(T</text>
<text x="77.8" y="32.1">= +25°C, V</text>
<text x="98.4" y="32.1">= V</text>
<text x="108" y="32.1">= 5V, R</text>
<text x="121.4" y="32.1">= 100kΩ, R</text>
<text x="142" y="32.1">= 10Ω, C</text>
<text x="157.7" y="32.1">= 1μF, C</text>
<text x="175.3" y="32.1">= 0.1μF, C</text>
<text x="193.8" y="32.1">= 1μF,</text>
<text x="22.1" y="45.9">V</text>
<text x="24.1" y="42.1">Symbol</text>
<text x="27" y="45.9">= 1.8V</text>
<text x="59.1" y="42.1">Parameter</text>
<text x="111.6" y="42.1">Condition</text>
<text x="147.5" y="42.1">Min</text>
<text x="162.6" y="42.1">Typ</text>
<text x="177.7" y="42.1">Max</text>
<text x="192.9" y="42.1">Unit</text>
<text x="26.4" y="51.8">t</text>
<text x="40" y="51.7">Output Turn-On Delay Time</text>
<text x="95.9" y="49.8">V</text>
<text x="95.9" y="53.7">V</text>
<text x="101.4" y="49.8">= 3.3V</text>
<text x="101.4" y="53.7">= 5V</text>
<text x="148.5" y="49.5">—</text>
<text x="148.5" y="53.4">—</text>
<text x="162.8" y="49.7">200</text>
<text x="162.8" y="53.7">130</text>
<text x="179" y="49.5">—</text>
<text x="179" y="53.4">—</text>
<text x="25.9" y="59.7">t</text>
<text x="40" y="59.6">Output Turn-Off Delay Time</text>
<text x="95.9" y="57.7">V</text>
<text x="101.4" y="57.7">= 3.3V</text>
<text x="148.5" y="57.4">—</text>
<text x="163.2" y="57.6">0.5</text>
<text x="179" y="57.4">—</text>
<text x="194.2" y="55.6">µs</text>
<text x="95.9" y="61.6">V</text>
<text x="95.9" y="65.6">V</text>
<text x="101.4" y="61.6">= 5V</text>
<text x="101.4" y="65.6">= 3.3V</text>
<text x="148.5" y="61.3">—</text>
<text x="148.5" y="65.2">—</text>
<text x="163.2" y="61.6">0.5</text>
<text x="163.2" y="65.5">0.4</text>
<text x="179" y="61.3">—</text>
<text x="179" y="65.2">—</text>
<text x="25.6" y="67.5">t</text>
<text x="40" y="67.4">Power Good Turn-On Time</text>
<text x="95.9" y="69.5">V</text>
<text x="101.4" y="69.5">= 5V</text>
<text x="148.5" y="69.2">—</text>
<text x="162.4" y="69.4">0.35</text>
<text x="179" y="69.2">—</text>
<text x="193.8" y="67.4">ms</text>
<text x="25.1" y="75.4">t</text>
<text x="40" y="75.2">Power Good Turn-Off Time</text>
<text x="95.9" y="73.4">V</text>
<text x="95.9" y="77.3">V</text>
<text x="101.4" y="73.4">= 3.3V</text>
<text x="101.4" y="77.3">= 5V</text>
<text x="148.5" y="73.1">—</text>
<text x="148.5" y="77">—</text>
<text x="163.6" y="73.3">20</text>
<text x="163.6" y="77.2">15</text>
<text x="179" y="73.1">—</text>
<text x="179" y="77">—</text>
<text x="194.2" y="75.2">ns</text>
<text x="27.2" y="83.1">SR</text>
<text x="40" y="83.1">Output Slew Rate</text>
<text x="95.9" y="81.2">V</text>
<text x="101.4" y="81.2">= 3.3V</text>
<text x="148.5" y="80.9">—</text>
<text x="163.6" y="81.1">17</text>
<text x="179" y="80.9">—</text>
<text x="192.9" y="83.1">kV/s</text>
<text x="22.1" y="89.1">V</text>
<text x="27" y="89.1">= 12V</text>
<text x="95.9" y="85.1">V</text>
<text x="101.4" y="85.1">= 5V</text>
<text x="148.5" y="84.8">—</text>
<text x="163.6" y="85.1">17</text>
<text x="179" y="84.8">—</text>
<text x="26.4" y="95">t</text>
<text x="40" y="94.9">Output Turn-On Delay Time</text>
<text x="95.9" y="93">V</text>
<text x="101.4" y="93">= 3.3V</text>
<text x="148.5" y="92.7">—</text>
<text x="162.8" y="92.9">170</text>
<text x="179" y="92.7">—</text>
<text x="95.9" y="96.9">V</text>
<text x="95.9" y="100.9">V</text>
<text x="101.4" y="96.9">= 5V</text>
<text x="101.4" y="100.9">= 3.3V</text>
<text x="148.5" y="96.6">—</text>
<text x="148.5" y="100.6">—</text>
<text x="162.8" y="96.8">110</text>
<text x="163.2" y="100.8">0.6</text>
<text x="179" y="96.6">—</text>
<text x="179" y="100.6">—</text>
<text x="194.2" y="98.8">µs</text>
<text x="25.9" y="102.8">t</text>
<text x="40" y="102.8">Output Turn-Off Delay Time</text>
<text x="95.9" y="104.8">V</text>
<text x="101.4" y="104.8">= 5V</text>
<text x="148.5" y="104.5">—</text>
<text x="162.4" y="104.7">0.55</text>
<text x="179" y="104.5">—</text>
<text x="25.6" y="110.7">t</text>
<text x="40" y="110.6">Power Good Turn-On Time</text>
<text x="95.9" y="108.7">V</text>
<text x="95.9" y="112.7">V</text>
<text x="101.4" y="108.7">= 3.3V</text>
<text x="101.4" y="112.7">= 5V</text>
<text x="148.5" y="108.4">—</text>
<text x="148.5" y="112.3">—</text>
<text x="163.2" y="108.6">0.6</text>
<text x="163.2" y="112.5">0.5</text>
<text x="179" y="108.4">—</text>
<text x="179" y="112.3">—</text>
<text x="193.8" y="110.6">ms</text>
<text x="25.1" y="118.5">t</text>
<text x="40" y="118.4">Power Good Turn-Off Time</text>
<text x="95.9" y="116.6">V</text>
<text x="101.4" y="116.6">= 3.3V</text>
<text x="148.5" y="116.3">—</text>
<text x="163.6" y="116.5">20</text>
<text x="179" y="116.3">—</text>
<text x="194.2" y="118.4">ns</text>
<text x="95.9" y="120.5">V</text>
<text x="95.9" y="124.4">V</text>
<text x="101.4" y="120.5">= 5V</text>
<text x="101.4" y="124.4">= 3.3V</text>
<text x="148.5" y="120.2">—</text>
<text x="148.5" y="124.1">—</text>
<text x="163.6" y="120.4">15</text>
<text x="163.6" y="124.3">43</text>
<text x="179" y="120.2">—</text>
<text x="179" y="124.1">—</text>
<text x="27.2" y="126.3">SR</text>
<text x="40" y="126.3">Output Slew Rate</text>
<text x="95.9" y="128.3">V</text>
<text x="101.4" y="128.3">= 5V</text>
<text x="148.5" y="128">—</text>
<text x="163.6" y="128.2">43</text>
<text x="179" y="128">—</text>
<text x="192.9" y="126.3">kV/s</text>
<text x="91.8" y="216">Figure 1. Timing Diagram</text>
<text x="100.3" y="268.7">www.diodes.com</text>
<text x="107.5" y="265.5">5 of 12</text>
</g>
<text font-size="2.8" fill="#231f20" x="190.1" y="265.8">June 2024</text>
<text font-size="2.5" x="20.4" y="269.2">Document number: DS42234 Rev. 5 - 2</text>
<g font-size="2.4" fill="#5b9bd5">
<text x="58" y="160.2">OND</text>
<text x="82.6" y="160.2">R</text>
<text x="79.2" y="197.8">PGON</text>
</g>
<g font-size="2.1">
<text x="75.6" y="32.2">A</text>
<text x="91.6" y="32.2">TERM</text>
<text x="102.7" y="32.2">VCC</text>
<text x="117.5" y="32.2">PG</text>
<text x="135.7" y="32.2">VOUT</text>
<text x="153.4" y="32.2">VIN</text>
<text x="168.6" y="32.2">VOUT</text>
<text x="188.6" y="32.2">VCC</text>
<text x="22.4" y="36.1">BLEED</text>
<text x="24.1" y="46.1">IN</text>
<text x="27.2" y="52">OND</text>
<text x="97.8" y="50">CC</text>
<text x="97.8" y="53.9">CC</text>
<text x="26.7" y="59.9">OFFD</text>
<text x="97.8" y="57.9">CC</text>
<text x="97.8" y="61.8">CC</text>
<text x="97.8" y="65.8">CC</text>
<text x="26.4" y="67.7">PGON</text>
<text x="97.8" y="69.6">CC</text>
<text x="25.9" y="75.5">PGOFF</text>
<text x="97.8" y="73.6">CC</text>
<text x="97.8" y="77.5">CC</text>
<text x="97.8" y="81.4">CC</text>
<text x="24.1" y="89.2">IN</text>
<text x="97.8" y="85.3">CC</text>
<text x="27.2" y="95.1">OND</text>
<text x="97.8" y="93.2">CC</text>
<text x="97.8" y="97.1">CC</text>
<text x="97.8" y="101.1">CC</text>
<text x="26.7" y="103">OFFD</text>
<text x="97.8" y="105">CC</text>
<text x="26.4" y="110.8">PGON</text>
<text x="97.8" y="108.9">CC</text>
<text x="97.8" y="112.8">CC</text>
<text x="25.9" y="118.7">PGOFF</text>
<text x="97.8" y="116.7">CC</text>
<text x="97.8" y="120.7">CC</text>
<text x="97.8" y="124.6">CC</text>
<text x="97.8" y="128.5">CC</text>
<text x="146.7" y="268.4">© 2024 Copyright Diodes Incorporated. All Rights Reserved.</text>
</g>
<g font-size="2" fill="#5b9bd5">
<text x="159.8" y="162.7">OFFD</text>
<text x="170.2" y="195.1">PGOFF</text>
</g>
</g></defs>
<path d="M163.9 14.1h39.2v7.3h-39.2z" fill="none" stroke="#000" stroke-width=".26"/>
<g fill="#000">
<path d="M19.8 27.2h183.7v.5h-183.7z" fill-rule="evenodd"/>
<path d="M19.8 37h183.7v.5h-183.7z" fill-rule="evenodd"/>
<path d="M20 38.9h.2v.6h-.2z" fill-rule="evenodd"/>
<path d="M20 38.9h.5v.2h-.5z" fill-rule="evenodd"/>
<path d="M20.3 39.3h.2v.2h-.2z" fill-rule="evenodd"/>
<path d="M20.3 39.3h.2v.1h-.2z" fill-rule="evenodd"/>
<path d="M37.9 39.4l.3 .1z" fill-rule="evenodd"/>
<path d="M37.9 38.9h.5v.2h-.5z" fill-rule="evenodd"/>
<path d="M37.9 39.3h.5v.1h-.5z" fill-rule="evenodd"/>
<path d="M93.9 39.4l.2 .1z" fill-rule="evenodd"/>
<path d="M93.9 38.9h.5v.2h-.5z" fill-rule="evenodd"/>
<path d="M93.9 39.3h.5v.1h-.5z" fill-rule="evenodd"/>
<path d="M142.2 39.4l.2 .1z" fill-rule="evenodd"/>
<path d="M142.2 38.9h.5v.2h-.5z" fill-rule="evenodd"/>
<path d="M142.2 39.3h.5v.1h-.5z" fill-rule="evenodd"/>
<path d="M157.4 39.4l.3 .1z" fill-rule="evenodd"/>
<path d="M157.4 38.9h.5v.2h-.5z" fill-rule="evenodd"/>
<path d="M157.4 39.3h.5v.1h-.5z" fill-rule="evenodd"/>
<path d="M172.7 39.4l.2 .1z" fill-rule="evenodd"/>
<path d="M172.7 38.9h.5v.2h-.5z" fill-rule="evenodd"/>
<path d="M172.7 39.3h.5v.1h-.5z" fill-rule="evenodd"/>
<path d="M188 39.4l.2 .1z" fill-rule="evenodd"/>
<path d="M188 38.9h.5v.2h-.5z" fill-rule="evenodd"/>
<path d="M188 39.3h.5v.1h-.5z" fill-rule="evenodd"/>
<path d="M203.1 38.9h.5v.2h-.5z" fill-rule="evenodd"/>
<path d="M203.1 39.3h.1v.2h-.1z" fill-rule="evenodd"/>
<path d="M203.1 39.3h.1v.1h-.1z" fill-rule="evenodd"/>
<path d="M203.4 38.9h.2v.6h-.2z" fill-rule="evenodd"/>
<path d="M20 42.7h.2v.2h-.2z" fill-rule="evenodd"/>
<path d="M20 46.6h.2v.2h-.2z" fill-rule="evenodd"/>
<path d="M20 50.5h.2v.3h-.2z" fill-rule="evenodd"/>
<path d="M20 54.5h.2v.2h-.2z" fill-rule="evenodd"/>
<path d="M20 58.4h.2v.3h-.2z" fill-rule="evenodd"/>
<path d="M20.3 42.7h.2v.2h-.2z" fill-rule="evenodd"/>
<path d="M20.3 46.6h.2v.2h-.2z" fill-rule="evenodd"/>
<path d="M20.3 50.5h.2v.3h-.2z" fill-rule="evenodd"/>
<path d="M20.3 54.5h.2v.2h-.2z" fill-rule="evenodd"/>
<path d="M20.3 58.4h.2v.3h-.2z" fill-rule="evenodd"/>
<path d="M37.9 42.7h.3v.2h-.3z" fill-rule="evenodd"/>
<path d="M37.9 46.6h.3v.2h-.3z" fill-rule="evenodd"/>
<path d="M37.9 50.5h.3v.3h-.3z" fill-rule="evenodd"/>
<path d="M37.9 54.5h.3v.2h-.3z" fill-rule="evenodd"/>
<path d="M37.9 58.4h.3v.3h-.3z" fill-rule="evenodd"/>
<path d="M93.9 42.7h.2v.2h-.2z" fill-rule="evenodd"/>
<path d="M93.9 46.6h.2v.2h-.2z" fill-rule="evenodd"/>
<path d="M93.9 50.5h.2v.3h-.2z" fill-rule="evenodd"/>
<path d="M93.9 54.5h.2v.2h-.2z" fill-rule="evenodd"/>
<path d="M93.9 58.4h.2v.3h-.2z" fill-rule="evenodd"/>
<path d="M142.2 42.7h.2v.2h-.2z" fill-rule="evenodd"/>
<path d="M142.2 46.6h.2v.2h-.2z" fill-rule="evenodd"/>
<path d="M142.2 50.5h.2v.3h-.2z" fill-rule="evenodd"/>
<path d="M142.2 54.5h.2v.2h-.2z" fill-rule="evenodd"/>
<path d="M142.2 58.4h.2v.3h-.2z" fill-rule="evenodd"/>
<path d="M157.4 42.7h.3v.2h-.3z" fill-rule="evenodd"/>
<path d="M157.4 46.6h.3v.2h-.3z" fill-rule="evenodd"/>
<path d="M157.4 50.5h.3v.3h-.3z" fill-rule="evenodd"/>
<path d="M157.4 54.5h.3v.2h-.3z" fill-rule="evenodd"/>
<path d="M157.4 58.4h.3v.3h-.3z" fill-rule="evenodd"/>
<path d="M172.7 42.7h.2v.2h-.2z" fill-rule="evenodd"/>
<path d="M172.7 46.6h.2v.2h-.2z" fill-rule="evenodd"/>
<path d="M172.7 50.5h.2v.3h-.2z" fill-rule="evenodd"/>
<path d="M172.7 54.5h.2v.2h-.2z" fill-rule="evenodd"/>
<path d="M172.7 58.4h.2v.3h-.2z" fill-rule="evenodd"/>
<path d="M188 42.7h.2v.2h-.2z" fill-rule="evenodd"/>
<path d="M188 46.6h.2v.2h-.2z" fill-rule="evenodd"/>
<path d="M188 50.5h.2v.3h-.2z" fill-rule="evenodd"/>
<path d="M188 54.5h.2v.2h-.2z" fill-rule="evenodd"/>
<path d="M188 58.4h.2v.3h-.2z" fill-rule="evenodd"/>
<path d="M203.1 42.7h.1v.2h-.1z" fill-rule="evenodd"/>
<path d="M203.1 46.6h.1v.2h-.1z" fill-rule="evenodd"/>
<path d="M203.1 50.5h.1v.3h-.1z" fill-rule="evenodd"/>
<path d="M203.1 54.5h.1v.2h-.1z" fill-rule="evenodd"/>
<path d="M203.1 58.4h.1v.3h-.1z" fill-rule="evenodd"/>
<path d="M203.4 42.7h.2v.2h-.2z" fill-rule="evenodd"/>
<path d="M203.4 46.6h.2v.2h-.2z" fill-rule="evenodd"/>
<path d="M203.4 50.5h.2v.3h-.2z" fill-rule="evenodd"/>
<path d="M203.4 54.5h.2v.2h-.2z" fill-rule="evenodd"/>
<path d="M203.4 58.4h.2v.3h-.2z" fill-rule="evenodd"/>
<path d="M20 62.3h.2v.3h-.2z" fill-rule="evenodd"/>
<path d="M20 66.3h.2v.2h-.2z" fill-rule="evenodd"/>
<path d="M20 70.2h.2v.2h-.2z" fill-rule="evenodd"/>
<path d="M20 74.1h.2v.2h-.2z" fill-rule="evenodd"/>
<path d="M20 78h.2v.2h-.2z" fill-rule="evenodd"/>
<path d="M20.3 62.3h.2v.3h-.2z" fill-rule="evenodd"/>
<path d="M20.3 66.3h.2v.2h-.2z" fill-rule="evenodd"/>
<path d="M20.3 70.2h.2v.2h-.2z" fill-rule="evenodd"/>
<path d="M20.3 74.1h.2v.2h-.2z" fill-rule="evenodd"/>
<path d="M20.3 78h.2v.2h-.2z" fill-rule="evenodd"/>
<path d="M37.9 62.3h.3v.3h-.3z" fill-rule="evenodd"/>
<path d="M37.9 66.3h.3v.2h-.3z" fill-rule="evenodd"/>
<path d="M37.9 70.2h.3v.2h-.3z" fill-rule="evenodd"/>
<path d="M37.9 74.1h.3v.2h-.3z" fill-rule="evenodd"/>
<path d="M37.9 78h.3v.2h-.3z" fill-rule="evenodd"/>
<path d="M93.9 62.3h.2v.3h-.2z" fill-rule="evenodd"/>
<path d="M93.9 66.3h.2v.2h-.2z" fill-rule="evenodd"/>
<path d="M93.9 70.2h.2v.2h-.2z" fill-rule="evenodd"/>
<path d="M93.9 74.1h.2v.2h-.2z" fill-rule="evenodd"/>
<path d="M93.9 78h.2v.2h-.2z" fill-rule="evenodd"/>
<path d="M142.2 62.3h.2v.3h-.2z" fill-rule="evenodd"/>
<path d="M142.2 66.3h.2v.2h-.2z" fill-rule="evenodd"/>
<path d="M142.2 70.2h.2v.2h-.2z" fill-rule="evenodd"/>
<path d="M142.2 74.1h.2v.2h-.2z" fill-rule="evenodd"/>
<path d="M142.2 78h.2v.2h-.2z" fill-rule="evenodd"/>
<path d="M157.4 62.3h.3v.3h-.3z" fill-rule="evenodd"/>
<path d="M157.4 66.3h.3v.2h-.3z" fill-rule="evenodd"/>
<path d="M157.4 70.2h.3v.2h-.3z" fill-rule="evenodd"/>
<path d="M157.4 74.1h.3v.2h-.3z" fill-rule="evenodd"/>
<path d="M157.4 78h.3v.2h-.3z" fill-rule="evenodd"/>
<path d="M172.7 62.3h.2v.3h-.2z" fill-rule="evenodd"/>
<path d="M172.7 66.3h.2v.2h-.2z" fill-rule="evenodd"/>
<path d="M172.7 70.2h.2v.2h-.2z" fill-rule="evenodd"/>
<path d="M172.7 74.1h.2v.2h-.2z" fill-rule="evenodd"/>
<path d="M172.7 78h.2v.2h-.2z" fill-rule="evenodd"/>
<path d="M188 62.3h.2v.3h-.2z" fill-rule="evenodd"/>
<path d="M188 66.3h.2v.2h-.2z" fill-rule="evenodd"/>
<path d="M188 70.2h.2v.2h-.2z" fill-rule="evenodd"/>
<path d="M188 74.1h.2v.2h-.2z" fill-rule="evenodd"/>
<path d="M188 78h.2v.2h-.2z" fill-rule="evenodd"/>
<path d="M203.1 62.3h.1v.3h-.1z" fill-rule="evenodd"/>
<path d="M203.1 66.3h.1v.2h-.1z" fill-rule="evenodd"/>
<path d="M203.1 70.2h.1v.2h-.1z" fill-rule="evenodd"/>
<path d="M203.1 74.1h.1v.2h-.1z" fill-rule="evenodd"/>
<path d="M203.1 78h.1v.2h-.1z" fill-rule="evenodd"/>
<path d="M203.4 62.3h.2v.3h-.2z" fill-rule="evenodd"/>
<path d="M203.4 66.3h.2v.2h-.2z" fill-rule="evenodd"/>
<path d="M203.4 70.2h.2v.2h-.2z" fill-rule="evenodd"/>
<path d="M203.4 74.1h.2v.2h-.2z" fill-rule="evenodd"/>
<path d="M203.4 78h.2v.2h-.2z" fill-rule="evenodd"/>
<path d="M20 81.9h.2v.3h-.2z" fill-rule="evenodd"/>
<path d="M20 85.8h.2v.3h-.2z" fill-rule="evenodd"/>
<path d="M20 89.8h.2v.2h-.2z" fill-rule="evenodd"/>
<path d="M20 93.7h.2v.2h-.2z" fill-rule="evenodd"/>
<path d="M20 97.7h.2v.2h-.2z" fill-rule="evenodd"/>
<path d="M20.3 81.9h.2v.3h-.2z" fill-rule="evenodd"/>
<path d="M20.3 85.8h.2v.3h-.2z" fill-rule="evenodd"/>
<path d="M20.3 89.8h.2v.2h-.2z" fill-rule="evenodd"/>
<path d="M20.3 93.7h.2v.2h-.2z" fill-rule="evenodd"/>
<path d="M20.3 97.7h.2v.2h-.2z" fill-rule="evenodd"/>
<path d="M37.9 81.9h.3v.3h-.3z" fill-rule="evenodd"/>
<path d="M37.9 85.8h.3v.3h-.3z" fill-rule="evenodd"/>
<path d="M37.9 89.8h.3v.2h-.3z" fill-rule="evenodd"/>
<path d="M37.9 93.7h.3v.2h-.3z" fill-rule="evenodd"/>
<path d="M37.9 97.7h.3v.2h-.3z" fill-rule="evenodd"/>
<path d="M93.9 81.9h.2v.3h-.2z" fill-rule="evenodd"/>
<path d="M93.9 85.8h.2v.3h-.2z" fill-rule="evenodd"/>
<path d="M93.9 89.8h.2v.2h-.2z" fill-rule="evenodd"/>
<path d="M93.9 93.7h.2v.2h-.2z" fill-rule="evenodd"/>
<path d="M93.9 97.7h.2v.2h-.2z" fill-rule="evenodd"/>
<path d="M142.2 81.9h.2v.3h-.2z" fill-rule="evenodd"/>
<path d="M142.2 85.8h.2v.3h-.2z" fill-rule="evenodd"/>
<path d="M142.2 89.8h.2v.2h-.2z" fill-rule="evenodd"/>
<path d="M142.2 93.7h.2v.2h-.2z" fill-rule="evenodd"/>
<path d="M142.2 97.7h.2v.2h-.2z" fill-rule="evenodd"/>
<path d="M157.4 81.9h.3v.3h-.3z" fill-rule="evenodd"/>
<path d="M157.4 85.8h.3v.3h-.3z" fill-rule="evenodd"/>
<path d="M157.4 89.8h.3v.2h-.3z" fill-rule="evenodd"/>
<path d="M157.4 93.7h.3v.2h-.3z" fill-rule="evenodd"/>
<path d="M157.4 97.7h.3v.2h-.3z" fill-rule="evenodd"/>
<path d="M172.7 81.9h.2v.3h-.2z" fill-rule="evenodd"/>
<path d="M172.7 85.8h.2v.3h-.2z" fill-rule="evenodd"/>
<path d="M172.7 89.8h.2v.2h-.2z" fill-rule="evenodd"/>
<path d="M172.7 93.7h.2v.2h-.2z" fill-rule="evenodd"/>
<path d="M172.7 97.7h.2v.2h-.2z" fill-rule="evenodd"/>
<path d="M188 81.9h.2v.3h-.2z" fill-rule="evenodd"/>
<path d="M188 85.8h.2v.3h-.2z" fill-rule="evenodd"/>
<path d="M188 89.8h.2v.2h-.2z" fill-rule="evenodd"/>
<path d="M188 93.7h.2v.2h-.2z" fill-rule="evenodd"/>
<path d="M188 97.7h.2v.2h-.2z" fill-rule="evenodd"/>
<path d="M203.1 81.9h.1v.3h-.1z" fill-rule="evenodd"/>
<path d="M203.1 85.8h.1v.3h-.1z" fill-rule="evenodd"/>
<path d="M203.1 89.8h.1v.2h-.1z" fill-rule="evenodd"/>
<path d="M203.1 93.7h.1v.2h-.1z" fill-rule="evenodd"/>
<path d="M203.1 97.7h.1v.2h-.1z" fill-rule="evenodd"/>
<path d="M203.4 81.9h.2v.3h-.2z" fill-rule="evenodd"/>
<path d="M203.4 85.8h.2v.3h-.2z" fill-rule="evenodd"/>
<path d="M203.4 89.8h.2v.2h-.2z" fill-rule="evenodd"/>
<path d="M203.4 93.7h.2v.2h-.2z" fill-rule="evenodd"/>
<path d="M203.4 97.7h.2v.2h-.2z" fill-rule="evenodd"/>
<path d="M20 101.6h.2v.2h-.2z" fill-rule="evenodd"/>
<path d="M20 105.5h.2v.3h-.2z" fill-rule="evenodd"/>
<path d="M20 109.4h.2v.3h-.2z" fill-rule="evenodd"/>
<path d="M20 113.3h.2v.3h-.2z" fill-rule="evenodd"/>
<path d="M20 117.2h.2v.3h-.2z" fill-rule="evenodd"/>
<path d="M20.3 101.6h.2v.2h-.2z" fill-rule="evenodd"/>
<path d="M20.3 105.5h.2v.3h-.2z" fill-rule="evenodd"/>
<path d="M20.3 109.4h.2v.3h-.2z" fill-rule="evenodd"/>
<path d="M20.3 113.3h.2v.3h-.2z" fill-rule="evenodd"/>
<path d="M20.3 117.2h.2v.3h-.2z" fill-rule="evenodd"/>
<path d="M37.9 101.6h.3v.2h-.3z" fill-rule="evenodd"/>
<path d="M37.9 105.5h.3v.3h-.3z" fill-rule="evenodd"/>
<path d="M37.9 109.4h.3v.3h-.3z" fill-rule="evenodd"/>
<path d="M37.9 113.3h.3v.3h-.3z" fill-rule="evenodd"/>
<path d="M37.9 117.2h.3v.3h-.3z" fill-rule="evenodd"/>
<path d="M93.9 101.6h.2v.2h-.2z" fill-rule="evenodd"/>
<path d="M93.9 105.5h.2v.3h-.2z" fill-rule="evenodd"/>
<path d="M93.9 109.4h.2v.3h-.2z" fill-rule="evenodd"/>
<path d="M93.9 113.3h.2v.3h-.2z" fill-rule="evenodd"/>
<path d="M93.9 117.2h.2v.3h-.2z" fill-rule="evenodd"/>
<path d="M142.2 101.6h.2v.2h-.2z" fill-rule="evenodd"/>
<path d="M142.2 105.5h.2v.3h-.2z" fill-rule="evenodd"/>
<path d="M142.2 109.4h.2v.3h-.2z" fill-rule="evenodd"/>
<path d="M142.2 113.3h.2v.3h-.2z" fill-rule="evenodd"/>
<path d="M142.2 117.2h.2v.3h-.2z" fill-rule="evenodd"/>
<path d="M157.4 101.6h.3v.2h-.3z" fill-rule="evenodd"/>
<path d="M157.4 105.5h.3v.3h-.3z" fill-rule="evenodd"/>
<path d="M157.4 109.4h.3v.3h-.3z" fill-rule="evenodd"/>
<path d="M157.4 113.3h.3v.3h-.3z" fill-rule="evenodd"/>
<path d="M157.4 117.2h.3v.3h-.3z" fill-rule="evenodd"/>
<path d="M172.7 101.6h.2v.2h-.2z" fill-rule="evenodd"/>
<path d="M172.7 105.5h.2v.3h-.2z" fill-rule="evenodd"/>
<path d="M172.7 109.4h.2v.3h-.2z" fill-rule="evenodd"/>
<path d="M172.7 113.3h.2v.3h-.2z" fill-rule="evenodd"/>
<path d="M172.7 117.2h.2v.3h-.2z" fill-rule="evenodd"/>
<path d="M188 101.6h.2v.2h-.2z" fill-rule="evenodd"/>
<path d="M188 105.5h.2v.3h-.2z" fill-rule="evenodd"/>
<path d="M188 109.4h.2v.3h-.2z" fill-rule="evenodd"/>
<path d="M188 113.3h.2v.3h-.2z" fill-rule="evenodd"/>
<path d="M188 117.2h.2v.3h-.2z" fill-rule="evenodd"/>
<path d="M203.1 101.6h.1v.2h-.1z" fill-rule="evenodd"/>
<path d="M203.1 105.5h.1v.3h-.1z" fill-rule="evenodd"/>
<path d="M203.1 109.4h.1v.3h-.1z" fill-rule="evenodd"/>
<path d="M203.1 113.3h.1v.3h-.1z" fill-rule="evenodd"/>
<path d="M203.1 117.2h.1v.3h-.1z" fill-rule="evenodd"/>
<path d="M203.4 101.6h.2v.2h-.2z" fill-rule="evenodd"/>
<path d="M203.4 105.5h.2v.3h-.2z" fill-rule="evenodd"/>
<path d="M203.4 109.4h.2v.3h-.2z" fill-rule="evenodd"/>
<path d="M203.4 113.3h.2v.3h-.2z" fill-rule="evenodd"/>
<path d="M203.4 117.2h.2v.3h-.2z" fill-rule="evenodd"/>
<path d="M20 121.2h.2v.2h-.2z" fill-rule="evenodd"/>
<path d="M20 125.1h.2v.2h-.2z" fill-rule="evenodd"/>
<path d="M20 129h.2v.5h-.2z" fill-rule="evenodd"/>
<path d="M20 129.3h.5v.2h-.5z" fill-rule="evenodd"/>
<path d="M20.3 121.2h.2v.2h-.2z" fill-rule="evenodd"/>
<path d="M20.3 125.1h.2v.2h-.2z" fill-rule="evenodd"/>
<path d="M20.3 129h.2v.2h-.2z" fill-rule="evenodd"/>
<path d="M20.3 129h.2v.2h-.2z" fill-rule="evenodd"/>
<path d="M37.9 121.2h.3v.2h-.3z" fill-rule="evenodd"/>
<path d="M37.9 125.1h.3v.2h-.3z" fill-rule="evenodd"/>
<path d="M37.9 129h.5v.2h-.5z" fill-rule="evenodd"/>
<path d="M37.9 129.3h.5v.2h-.5z" fill-rule="evenodd"/>
<path d="M93.9 121.2h.2v.2h-.2z" fill-rule="evenodd"/>
<path d="M93.9 125.1h.2v.2h-.2z" fill-rule="evenodd"/>
<path d="M93.9 129h.5v.2h-.5z" fill-rule="evenodd"/>
<path d="M93.9 129.3h.5v.2h-.5z" fill-rule="evenodd"/>
<path d="M142.2 121.2h.2v.2h-.2z" fill-rule="evenodd"/>
<path d="M142.2 125.1h.2v.2h-.2z" fill-rule="evenodd"/>
<path d="M142.2 129h.5v.2h-.5z" fill-rule="evenodd"/>
<path d="M142.2 129.3h.5v.2h-.5z" fill-rule="evenodd"/>
<path d="M157.4 121.2h.3v.2h-.3z" fill-rule="evenodd"/>
<path d="M157.4 125.1h.3v.2h-.3z" fill-rule="evenodd"/>
<path d="M157.4 129h.5v.2h-.5z" fill-rule="evenodd"/>
<path d="M157.4 129.3h.5v.2h-.5z" fill-rule="evenodd"/>
<path d="M172.7 121.2h.2v.2h-.2z" fill-rule="evenodd"/>
<path d="M172.7 125.1h.2v.2h-.2z" fill-rule="evenodd"/>
<path d="M172.7 129h.5v.2h-.5z" fill-rule="evenodd"/>
<path d="M172.7 129.3h.5v.2h-.5z" fill-rule="evenodd"/>
<path d="M188 121.2h.2v.2h-.2z" fill-rule="evenodd"/>
<path d="M188 125.1h.2v.2h-.2z" fill-rule="evenodd"/>
<path d="M188 129h.5v.2h-.5z" fill-rule="evenodd"/>
<path d="M188 129.3h.5v.2h-.5z" fill-rule="evenodd"/>
<path d="M203.1 121.2h.1v.2h-.1z" fill-rule="evenodd"/>
<path d="M203.1 125.1h.1v.2h-.1z" fill-rule="evenodd"/>
<path d="M203.1 129.3h.5v.2h-.5z" fill-rule="evenodd"/>
<path d="M203.1 129h.1v.2h-.1z" fill-rule="evenodd"/>
<path d="M203.1 129h.1v.2h-.1z" fill-rule="evenodd"/>
<path d="M203.4 121.2h.2v.2h-.2z" fill-rule="evenodd"/>
<path d="M203.4 125.1h.2v.2h-.2z" fill-rule="evenodd"/>
<path d="M203.4 129h.2v.5h-.2z" fill-rule="evenodd"/>
</g>
<g fill="none" stroke="#000" stroke-width=".2">
<path d="M20.1 39.5v3.2M20.4 39.5v3.2M20.5 39h17.4M20.5 39.3h17.4M38.4 39h55.5M38.4 39.3h55.5M94.4 39h47.8M94.4 39.3h47.8M142.7 39h14.7M142.7 39.3h14.7M157.9 39h14.8M157.9 39.3h14.8"/>
<path d="M173.2 39h14.8M173.2 39.3h14.8M188.5 39h14.6M188.5 39.3h14.6M203.2 39.5v3.2M203.5 39.5v3.2M20.1 42.9v3.7M20.1 46.8v3.7M20.1 50.8v3.7M20.1 54.7v3.7M20.1 58.7v3.6M20.4 42.9v3.7"/>
<path d="M20.4 46.8v3.7M20.4 50.8v3.7M20.4 54.7v3.7M20.4 58.7v3.6M203.2 42.9v3.7M203.2 46.8v3.7M203.2 50.8v3.7M203.2 54.7v3.7M203.2 58.7v3.6M203.5 42.9v3.7M203.5 46.8v3.7M203.5 50.8v3.7"/>
<path d="M203.5 54.7v3.7M203.5 58.7v3.6M20.1 62.6v3.7M20.1 66.5v3.7M20.1 70.4v3.7M20.1 74.3v3.7M20.1 78.2v3.7M20.4 62.6v3.7M20.4 66.5v3.7M20.4 70.4v3.7M20.4 74.3v3.7M20.4 78.2v3.7"/>
<path d="M203.2 62.6v3.7M203.2 66.5v3.7M203.2 70.4v3.7M203.2 74.3v3.7M203.2 78.2v3.7M203.5 62.6v3.7M203.5 66.5v3.7M203.5 70.4v3.7M203.5 74.3v3.7M203.5 78.2v3.7M20.1 82.2v3.6M20.1 86.1v3.7"/>
<path d="M20.1 90v3.7M20.1 93.9v3.8M20.1 97.9v3.7M20.4 82.2v3.6M20.4 86.1v3.7M20.4 90v3.7M20.4 93.9v3.8M20.4 97.9v3.7M203.2 82.2v3.6M203.2 86.1v3.7M203.2 90v3.7M203.2 93.9v3.8"/>
<path d="M203.2 97.9v3.7M203.5 82.2v3.6M203.5 86.1v3.7M203.5 90v3.7M203.5 93.9v3.8M203.5 97.9v3.7M20.1 101.8v3.7M20.1 105.8v3.6M20.1 109.7v3.6M20.1 113.6v3.6M20.1 117.5v3.7M20.4 101.8v3.7"/>
<path d="M20.4 105.8v3.6M20.4 109.7v3.6M20.4 113.6v3.6M20.4 117.5v3.7M203.2 101.8v3.7M203.2 105.8v3.6M203.2 109.7v3.6M203.2 113.6v3.6M203.2 117.5v3.7M203.5 101.8v3.7M203.5 105.8v3.6M203.5 109.7v3.6"/>
<path d="M203.5 113.6v3.6M203.5 117.5v3.7M20.1 121.4v3.7M20.1 125.3v3.7M20.4 121.4v3.7M20.4 125.3v3.7M20.5 129.4h17.4M20.5 129.1h17.4M38.4 129.4h55.5M38.4 129.1h55.5M94.4 129.4h47.8M94.4 129.1h47.8"/>
<path d="M142.7 129.4h14.7M142.7 129.1h14.7M157.9 129.4h14.8M157.9 129.1h14.8M173.2 129.4h14.8M173.2 129.1h14.8M188.5 129.4h14.6M188.5 129.1h14.6M203.2 121.4v3.7M203.2 125.3v3.7M203.5 121.4v3.7M203.5 125.3v3.7"/>
</g>
<g fill="none" stroke="#000" stroke-width=".25">
<path d="M38.1 39.5v3.2M94 39.5v3.2M142.3 39.5v3.2M157.5 39.5v3.2M172.8 39.5v3.2M188.1 39.5v3.2M20.5 42.8h17.4M20.5 46.7h17.4M20.5 54.6h17.4M38.1 46.8v3.7M38.1 50.8v3.7M38.1 54.7v3.7"/>
<path d="M38.1 58.7v3.6M38.2 42.8h55.7M38.2 46.7h55.7M38.2 54.6h55.7M94 46.8v3.7M94 50.8v3.7M94 54.7v3.7M94 58.7v3.6M94.1 42.8h48.1M94.1 46.7h48.1M94.1 50.6h48.1M94.1 54.6h48.1"/>
<path d="M94.1 58.6h48.1M142.3 46.8v3.7M142.3 50.8v3.7M142.3 54.7v3.7M142.3 58.7v3.6M142.4 42.8h15M142.4 46.7h15M142.4 50.6h15M142.4 54.6h15M142.4 58.6h15M157.5 46.8v3.7M157.5 50.8v3.7"/>
<path d="M157.5 54.7v3.7M157.5 58.7v3.6M157.7 42.8h15M157.7 46.7h15M157.7 50.6h15M157.7 54.6h15M157.7 58.6h15M172.8 46.8v3.7M172.8 50.8v3.7M172.8 54.7v3.7M172.8 58.7v3.6M172.9 42.8h15.1"/>
<path d="M172.9 46.7h15.1M172.9 50.6h15.1M172.9 54.6h15.1M172.9 58.6h15.1M188.1 46.8v3.7M188.1 50.8v3.7M188.1 54.7v3.7M188.1 58.7v3.6M188.2 42.8h14.9M188.2 46.7h14.9M20.5 62.4h17.4M20.5 70.3h17.4"/>
<path d="M20.5 78.1h17.4M38.1 62.6v3.7M38.1 66.5v3.7M38.1 70.4v3.7M38.1 74.3v3.7M38.1 78.2v3.7M38.2 62.4h55.7M38.2 70.3h55.7M38.2 78.1h55.7M94 62.6v3.7M94 66.5v3.7M94 70.4v3.7"/>
<path d="M94 74.3v3.7M94 78.2v3.7M94.1 62.4h48.1M94.1 66.4h48.1M94.1 70.3h48.1M94.1 74.2h48.1M94.1 78.1h48.1M142.3 62.6v3.7M142.3 66.5v3.7M142.3 70.4v3.7M142.3 74.3v3.7M142.3 78.2v3.7"/>
<path d="M142.4 62.4h15M142.4 66.4h15M142.4 70.3h15M142.4 74.2h15M142.4 78.1h15M157.5 62.6v3.7M157.5 66.5v3.7M157.5 70.4v3.7M157.5 74.3v3.7M157.5 78.2v3.7M157.7 62.4h15M157.7 66.4h15"/>
<path d="M157.7 70.3h15M157.7 74.2h15M157.7 78.1h15M172.8 62.6v3.7M172.8 66.5v3.7M172.8 70.4v3.7M172.8 74.3v3.7M172.8 78.2v3.7M172.9 62.4h15.1M172.9 66.4h15.1M172.9 70.3h15.1M172.9 74.2h15.1"/>
<path d="M172.9 78.1h15.1M188.1 62.6v3.7M188.1 66.5v3.7M188.1 70.4v3.7M188.1 74.3v3.7M188.1 78.2v3.7M188.2 62.4h14.9M188.2 70.3h14.9M188.2 78.1h14.9M20.5 85.9h17.4M20.5 89.9h17.4M20.5 97.8h17.4"/>
<path d="M38.1 82.2v3.6M38.1 90v3.7M38.1 93.9v3.8M38.1 97.9v3.7M38.2 85.9h55.7M38.2 89.9h55.7M38.2 97.8h55.7M94 82.2v3.6M94 90v3.7M94 93.9v3.8M94 97.9v3.7M94.1 82h48.1"/>
<path d="M94.1 85.9h48.1M94.1 89.9h48.1M94.1 93.8h48.1M94.1 97.8h48.1M142.3 82.2v3.6M142.3 90v3.7M142.3 93.9v3.8M142.3 97.9v3.7M142.4 82h15M142.4 85.9h15M142.4 89.9h15M142.4 93.8h15"/>
<path d="M142.4 97.8h15M157.5 82.2v3.6M157.5 90v3.7M157.5 93.9v3.8M157.5 97.9v3.7M157.7 82h15M157.7 85.9h15M157.7 89.9h15M157.7 93.8h15M157.7 97.8h15M172.8 82.2v3.6M172.8 90v3.7"/>
<path d="M172.8 93.9v3.8M172.8 97.9v3.7M172.9 82h15.1M172.9 85.9h15.1M172.9 89.9h15.1M172.9 93.8h15.1M172.9 97.8h15.1M188.1 82.2v3.6M188.1 90v3.7M188.1 93.9v3.8M188.1 97.9v3.7M188.2 85.9h14.9"/>
<path d="M188.2 89.9h14.9M20.5 105.6h17.4M20.5 113.5h17.4M38.1 101.8v3.7M38.1 105.8v3.6M38.1 109.7v3.6M38.1 113.6v3.6M38.1 117.5v3.7M38.2 105.6h55.7M38.2 113.5h55.7M94 101.8v3.7M94 105.8v3.6"/>
<path d="M94 109.7v3.6M94 113.6v3.6M94 117.5v3.7M94.1 101.7h48.1M94.1 105.6h48.1M94.1 109.5h48.1M94.1 113.5h48.1M94.1 117.4h48.1M142.3 101.8v3.7M142.3 105.8v3.6M142.3 109.7v3.6M142.3 113.6v3.6"/>
<path d="M142.3 117.5v3.7M142.4 101.7h15M142.4 105.6h15M142.4 109.5h15M142.4 113.5h15M142.4 117.4h15M157.5 101.8v3.7M157.5 105.8v3.6M157.5 109.7v3.6M157.5 113.6v3.6M157.5 117.5v3.7M157.7 101.7h15"/>
<path d="M157.7 105.6h15M157.7 109.5h15M157.7 113.5h15M157.7 117.4h15M172.8 101.8v3.7M172.8 105.8v3.6M172.8 109.7v3.6M172.8 113.6v3.6M172.8 117.5v3.7M172.9 101.7h15.1M172.9 105.6h15.1M172.9 109.5h15.1"/>
<path d="M172.9 113.5h15.1M172.9 117.4h15.1M188.1 101.8v3.7M188.1 105.8v3.6M188.1 109.7v3.6M188.1 113.6v3.6M188.1 117.5v3.7M188.2 105.6h14.9M188.2 113.5h14.9M20.5 121.3h17.4M38.1 121.4v3.7M38.1 125.3v3.7"/>
<path d="M38.2 121.3h55.7M94 121.4v3.7M94 125.3v3.7M94.1 121.3h48.1M94.1 125.2h48.1M142.3 121.4v3.7M142.3 125.3v3.7M142.4 121.3h15M142.4 125.2h15M157.5 121.4v3.7M157.5 125.3v3.7M157.7 121.3h15"/>
<path d="M157.7 125.2h15M172.8 121.4v3.7M172.8 125.3v3.7M172.9 121.3h15.1M172.9 125.2h15.1M188.1 121.4v3.7M188.1 125.3v3.7M188.2 121.3h14.9"/>
</g>
<path d="M34 157.1h13.6l-.3 .2 6.6-20.1h102.2l5.3 20.1-.3-.2h23.7v.6h-23.9l-5.3-20.1 .3 .2h-101.8l.3-.2-6.6 20.1h-13.8zM35 184.3h30.8l-.1 .1 36.9-18.5h62.9l4.5 18.4-.3-.2h25.3v.6h-25.5l-4.5-18.4 .3 .2h-62.6h.1l-36.9 18.4h-30.9z" fill="#000"/>
<path d="M51.2 137.9v65.6M158.4 136.4v73.7M69.3 156.5v33.3M166 158.8v29.5" fill="none" stroke="#5b9bd5" stroke-width=".2" stroke-dasharray=".3 .5"/>
<path d="M44 148h14.4M150.8 148h15.3M90.2 168.8h14.4M161.7 171h10.3" fill="none" stroke="#5b9bd5" stroke-width=".2"/>
<path d="M52.7 161h15" fill="none" stroke="#5b9bd5" stroke-width=".38"/>
<g fill="#5b9bd5">
<path d="M51.2 161l2-1a2.29 2.29 0 0 0 0 2z" fill-rule="evenodd"/>
<path d="M67.2 160l2.1 1-2.1 1a2.28 2.28 0 0 0 0-2z" fill-rule="evenodd"/>
</g>
<path d="M159.8 163.9h4.7" fill="none" stroke="#5b9bd5" stroke-width=".38"/>
<g fill="#5b9bd5">
<path d="M158.3 163.9l2-1.1a2.3 2.3 0 0 0 0 2.1z" fill-rule="evenodd"/>
<path d="M164 162.8l2 1.1-2 1a2.3 2.3 0 0 0 0-2.1z" fill-rule="evenodd"/>
</g>
<path d="M64.9 182.6h8.7" fill="none" stroke="#5b9bd5" stroke-width=".25"/>
<path d="M97.4 156.5v33.3" fill="none" stroke="#5b9bd5" stroke-width=".25" stroke-dasharray=".3 .5"/>
<path d="M71.5 161h24.2" fill="none" stroke="#5b9bd5" stroke-width=".38"/>
<g fill="#5b9bd5">
<path d="M69.9 161l2.1-1a2.28 2.28 0 0 0 0 2z" fill-rule="evenodd"/>
<path d="M95.2 160l2 1-2 1a2.28 2.28 0 0 0 0-2z" fill-rule="evenodd"/>
</g>
<path d="M34.3 209.7h82.7l-.4 .3 4-14.5h40.7l4.9 13.9-.3-.2h29.2v.6h-29.4l-4.9-13.9 .3 .2h-40.3l.3-.2-3.9 14.5h-82.9z" fill="#000"/>
<path d="M163.3 191.1l.1 19.1" fill="none" stroke="#5b9bd5" stroke-width=".25" stroke-dasharray=".3 .5"/>
<path d="M165.1 193.6h3M160.7 202.9h5.9" fill="none" stroke="#5b9bd5" stroke-width=".25"/>
<path d="M163.5 193.6l1.8-.9v1.8z" fill="#5b9bd5"/>
<path d="M153.6 193.6h3.2" fill="none" stroke="#5b9bd5" stroke-width=".25"/>
<path d="M156.6 192.7l1.8 .9-1.8 .9z" fill="#5b9bd5"/>
<path d="M115.4 202.6h7.2" fill="none" stroke="#5b9bd5" stroke-width=".25"/>
<path d="M119 193.5v16.7" fill="none" stroke="#5b9bd5" stroke-width=".25" stroke-dasharray=".3 .5"/>
<path d="M52.7 198.9h64.8" fill="none" stroke="#5b9bd5" stroke-width=".38"/>
<g fill="#5b9bd5">
<path d="M51.2 198.9l2-1.1a2.29 2.29 0 0 0 0 2.1z" fill-rule="evenodd"/>
<path d="M117 197.8l2 1.1-2 1a2.3 2.3 0 0 0 0-2.1z" fill-rule="evenodd"/>
</g>
<path d="M79.8 212.1h57.9v5.8h-57.9z" fill-rule="evenodd" fill="#fff"/>
<use href="#words"/>
</svg>
